VERSION 5.8 ;
BUSBITCHARS "[]" ;
DIVIDERCHAR "/" ;
UNITS
    DATABASE MICRONS 1000 ;
END UNITS

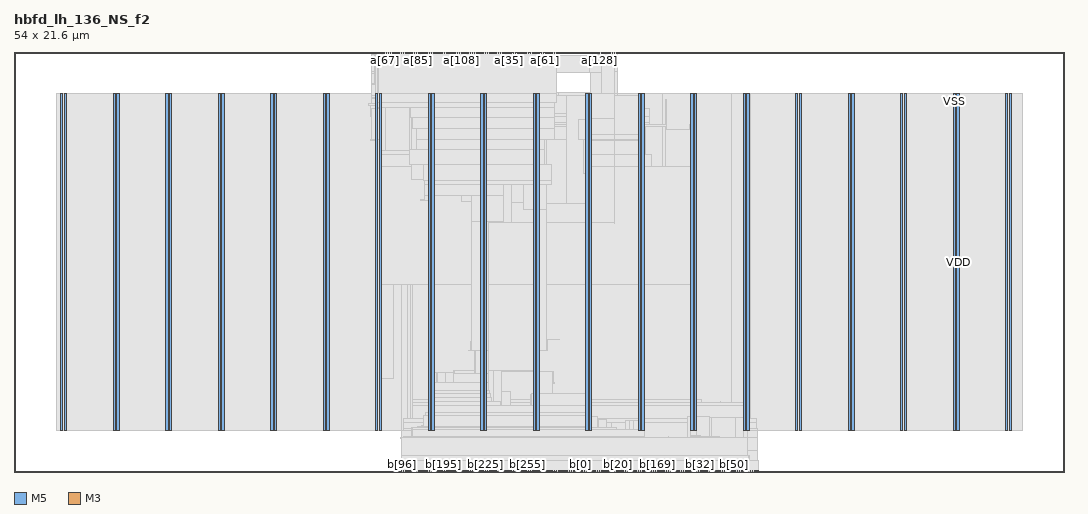
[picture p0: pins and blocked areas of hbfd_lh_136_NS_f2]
MACRO hbfd_lh_136_NS_f2
  FOREIGN hbfd_lh_136_NS_f2 0 0 ;
  CLASS BLOCK ;
  SIZE 54 BY 21.6 ;
  PIN a[0]
    DIRECTION INPUT ;
    USE SIGNAL ;
    PORT
      LAYER M5 ;
        RECT  24.912 21.516 24.936 21.6 ;
    END
  END a[0]
  PIN a[100]
    DIRECTION INPUT ;
    USE SIGNAL ;
    PORT
      LAYER M5 ;
        RECT  22.224 21.516 22.248 21.6 ;
    END
  END a[100]
  PIN a[101]
    DIRECTION INPUT ;
    USE SIGNAL ;
    PORT
      LAYER M5 ;
        RECT  22.32 21.516 22.344 21.6 ;
    END
  END a[101]
  PIN a[102]
    DIRECTION INPUT ;
    USE SIGNAL ;
    PORT
      LAYER M5 ;
        RECT  22.416 21.516 22.44 21.6 ;
    END
  END a[102]
  PIN a[103]
    DIRECTION INPUT ;
    USE SIGNAL ;
    PORT
      LAYER M5 ;
        RECT  22.512 21.516 22.536 21.6 ;
    END
  END a[103]
  PIN a[104]
    DIRECTION INPUT ;
    USE SIGNAL ;
    PORT
      LAYER M5 ;
        RECT  22.608 21.516 22.632 21.6 ;
    END
  END a[104]
  PIN a[105]
    DIRECTION INPUT ;
    USE SIGNAL ;
    PORT
      LAYER M5 ;
        RECT  22.704 21.516 22.728 21.6 ;
    END
  END a[105]
  PIN a[106]
    DIRECTION INPUT ;
    USE SIGNAL ;
    PORT
      LAYER M5 ;
        RECT  22.8 21.516 22.824 21.6 ;
    END
  END a[106]
  PIN a[107]
    DIRECTION INPUT ;
    USE SIGNAL ;
    PORT
      LAYER M5 ;
        RECT  22.896 21.516 22.92 21.6 ;
    END
  END a[107]
  PIN a[108]
    DIRECTION INPUT ;
    USE SIGNAL ;
    PORT
      LAYER M5 ;
        RECT  22.992 21.516 23.016 21.6 ;
    END
  END a[108]
  PIN a[109]
    DIRECTION INPUT ;
    USE SIGNAL ;
    PORT
      LAYER M5 ;
        RECT  23.088 21.516 23.112 21.6 ;
    END
  END a[109]
  PIN a[10]
    DIRECTION INPUT ;
    USE SIGNAL ;
    PORT
      LAYER M5 ;
        RECT  25.872 21.516 25.896 21.6 ;
    END
  END a[10]
  PIN a[110]
    DIRECTION INPUT ;
    USE SIGNAL ;
    PORT
      LAYER M5 ;
        RECT  23.184 21.516 23.208 21.6 ;
    END
  END a[110]
  PIN a[111]
    DIRECTION INPUT ;
    USE SIGNAL ;
    PORT
      LAYER M5 ;
        RECT  23.28 21.516 23.304 21.6 ;
    END
  END a[111]
  PIN a[112]
    DIRECTION INPUT ;
    USE SIGNAL ;
    PORT
      LAYER M5 ;
        RECT  23.376 21.516 23.4 21.6 ;
    END
  END a[112]
  PIN a[113]
    DIRECTION INPUT ;
    USE SIGNAL ;
    PORT
      LAYER M5 ;
        RECT  23.472 21.516 23.496 21.6 ;
    END
  END a[113]
  PIN a[114]
    DIRECTION INPUT ;
    USE SIGNAL ;
    PORT
      LAYER M5 ;
        RECT  23.568 21.516 23.592 21.6 ;
    END
  END a[114]
  PIN a[115]
    DIRECTION INPUT ;
    USE SIGNAL ;
    PORT
      LAYER M5 ;
        RECT  23.664 21.516 23.688 21.6 ;
    END
  END a[115]
  PIN a[116]
    DIRECTION INPUT ;
    USE SIGNAL ;
    PORT
      LAYER M5 ;
        RECT  23.76 21.516 23.784 21.6 ;
    END
  END a[116]
  PIN a[117]
    DIRECTION INPUT ;
    USE SIGNAL ;
    PORT
      LAYER M5 ;
        RECT  23.856 21.516 23.88 21.6 ;
    END
  END a[117]
  PIN a[118]
    DIRECTION INPUT ;
    USE SIGNAL ;
    PORT
      LAYER M5 ;
        RECT  23.952 21.516 23.976 21.6 ;
    END
  END a[118]
  PIN a[119]
    DIRECTION INPUT ;
    USE SIGNAL ;
    PORT
      LAYER M5 ;
        RECT  24.048 21.516 24.072 21.6 ;
    END
  END a[119]
  PIN a[11]
    DIRECTION INPUT ;
    USE SIGNAL ;
    PORT
      LAYER M5 ;
        RECT  25.968 21.516 25.992 21.6 ;
    END
  END a[11]
  PIN a[120]
    DIRECTION INPUT ;
    USE SIGNAL ;
    PORT
      LAYER M5 ;
        RECT  24.144 21.516 24.168 21.6 ;
    END
  END a[120]
  PIN a[121]
    DIRECTION INPUT ;
    USE SIGNAL ;
    PORT
      LAYER M5 ;
        RECT  24.24 21.516 24.264 21.6 ;
    END
  END a[121]
  PIN a[122]
    DIRECTION INPUT ;
    USE SIGNAL ;
    PORT
      LAYER M5 ;
        RECT  24.336 21.516 24.36 21.6 ;
    END
  END a[122]
  PIN a[123]
    DIRECTION INPUT ;
    USE SIGNAL ;
    PORT
      LAYER M5 ;
        RECT  24.432 21.516 24.456 21.6 ;
    END
  END a[123]
  PIN a[124]
    DIRECTION INPUT ;
    USE SIGNAL ;
    PORT
      LAYER M5 ;
        RECT  24.528 21.516 24.552 21.6 ;
    END
  END a[124]
  PIN a[125]
    DIRECTION INPUT ;
    USE SIGNAL ;
    PORT
      LAYER M5 ;
        RECT  24.624 21.516 24.648 21.6 ;
    END
  END a[125]
  PIN a[126]
    DIRECTION INPUT ;
    USE SIGNAL ;
    PORT
      LAYER M5 ;
        RECT  24.72 21.516 24.744 21.6 ;
    END
  END a[126]
  PIN a[127]
    DIRECTION INPUT ;
    USE SIGNAL ;
    PORT
      LAYER M5 ;
        RECT  24.816 21.516 24.84 21.6 ;
    END
  END a[127]
  PIN a[128]
    DIRECTION INPUT ;
    USE SIGNAL ;
    PORT
      LAYER M5 ;
        RECT  30.096 21.516 30.12 21.6 ;
    END
  END a[128]
  PIN a[129]
    DIRECTION INPUT ;
    USE SIGNAL ;
    PORT
      LAYER M5 ;
        RECT  30.192 21.516 30.216 21.6 ;
    END
  END a[129]
  PIN a[12]
    DIRECTION INPUT ;
    USE SIGNAL ;
    PORT
      LAYER M5 ;
        RECT  26.064 21.516 26.088 21.6 ;
    END
  END a[12]
  PIN a[130]
    DIRECTION INPUT ;
    USE SIGNAL ;
    PORT
      LAYER M5 ;
        RECT  30.288 21.516 30.312 21.6 ;
    END
  END a[130]
  PIN a[131]
    DIRECTION INPUT ;
    USE SIGNAL ;
    PORT
      LAYER M5 ;
        RECT  30.384 21.516 30.408 21.6 ;
    END
  END a[131]
  PIN a[132]
    DIRECTION INPUT ;
    USE SIGNAL ;
    PORT
      LAYER M5 ;
        RECT  30.48 21.516 30.504 21.6 ;
    END
  END a[132]
  PIN a[133]
    DIRECTION INPUT ;
    USE SIGNAL ;
    PORT
      LAYER M5 ;
        RECT  30.576 21.516 30.6 21.6 ;
    END
  END a[133]
  PIN a[134]
    DIRECTION INPUT ;
    USE SIGNAL ;
    PORT
      LAYER M5 ;
        RECT  30.672 21.516 30.696 21.6 ;
    END
  END a[134]
  PIN a[135]
    DIRECTION INPUT ;
    USE SIGNAL ;
    PORT
      LAYER M5 ;
        RECT  30.768 21.516 30.792 21.6 ;
    END
  END a[135]
  PIN a[13]
    DIRECTION INPUT ;
    USE SIGNAL ;
    PORT
      LAYER M5 ;
        RECT  26.16 21.516 26.184 21.6 ;
    END
  END a[13]
  PIN a[14]
    DIRECTION INPUT ;
    USE SIGNAL ;
    PORT
      LAYER M5 ;
        RECT  26.256 21.516 26.28 21.6 ;
    END
  END a[14]
  PIN a[15]
    DIRECTION INPUT ;
    USE SIGNAL ;
    PORT
      LAYER M5 ;
        RECT  26.352 21.516 26.376 21.6 ;
    END
  END a[15]
  PIN a[16]
    DIRECTION INPUT ;
    USE SIGNAL ;
    PORT
      LAYER M5 ;
        RECT  26.448 21.516 26.472 21.6 ;
    END
  END a[16]
  PIN a[17]
    DIRECTION INPUT ;
    USE SIGNAL ;
    PORT
      LAYER M5 ;
        RECT  26.544 21.516 26.568 21.6 ;
    END
  END a[17]
  PIN a[18]
    DIRECTION INPUT ;
    USE SIGNAL ;
    PORT
      LAYER M5 ;
        RECT  26.64 21.516 26.664 21.6 ;
    END
  END a[18]
  PIN a[19]
    DIRECTION INPUT ;
    USE SIGNAL ;
    PORT
      LAYER M5 ;
        RECT  26.736 21.516 26.76 21.6 ;
    END
  END a[19]
  PIN a[1]
    DIRECTION INPUT ;
    USE SIGNAL ;
    PORT
      LAYER M5 ;
        RECT  25.008 21.516 25.032 21.6 ;
    END
  END a[1]
  PIN a[20]
    DIRECTION INPUT ;
    USE SIGNAL ;
    PORT
      LAYER M5 ;
        RECT  26.832 21.516 26.856 21.6 ;
    END
  END a[20]
  PIN a[21]
    DIRECTION INPUT ;
    USE SIGNAL ;
    PORT
      LAYER M5 ;
        RECT  26.928 21.516 26.952 21.6 ;
    END
  END a[21]
  PIN a[22]
    DIRECTION INPUT ;
    USE SIGNAL ;
    PORT
      LAYER M5 ;
        RECT  27.024 21.516 27.048 21.6 ;
    END
  END a[22]
  PIN a[23]
    DIRECTION INPUT ;
    USE SIGNAL ;
    PORT
      LAYER M5 ;
        RECT  27.12 21.516 27.144 21.6 ;
    END
  END a[23]
  PIN a[24]
    DIRECTION INPUT ;
    USE SIGNAL ;
    PORT
      LAYER M5 ;
        RECT  27.216 21.516 27.24 21.6 ;
    END
  END a[24]
  PIN a[25]
    DIRECTION INPUT ;
    USE SIGNAL ;
    PORT
      LAYER M5 ;
        RECT  27.312 21.516 27.336 21.6 ;
    END
  END a[25]
  PIN a[26]
    DIRECTION INPUT ;
    USE SIGNAL ;
    PORT
      LAYER M5 ;
        RECT  27.408 21.516 27.432 21.6 ;
    END
  END a[26]
  PIN a[27]
    DIRECTION INPUT ;
    USE SIGNAL ;
    PORT
      LAYER M5 ;
        RECT  27.504 21.516 27.528 21.6 ;
    END
  END a[27]
  PIN a[28]
    DIRECTION INPUT ;
    USE SIGNAL ;
    PORT
      LAYER M5 ;
        RECT  27.6 21.516 27.624 21.6 ;
    END
  END a[28]
  PIN a[29]
    DIRECTION INPUT ;
    USE SIGNAL ;
    PORT
      LAYER M5 ;
        RECT  27.696 21.516 27.72 21.6 ;
    END
  END a[29]
  PIN a[2]
    DIRECTION INPUT ;
    USE SIGNAL ;
    PORT
      LAYER M5 ;
        RECT  25.104 21.516 25.128 21.6 ;
    END
  END a[2]
  PIN a[30]
    DIRECTION INPUT ;
    USE SIGNAL ;
    PORT
      LAYER M5 ;
        RECT  27.792 21.516 27.816 21.6 ;
    END
  END a[30]
  PIN a[31]
    DIRECTION INPUT ;
    USE SIGNAL ;
    PORT
      LAYER M5 ;
        RECT  27.888 21.516 27.912 21.6 ;
    END
  END a[31]
  PIN a[32]
    DIRECTION INPUT ;
    USE SIGNAL ;
    PORT
      LAYER M3 ;
        RECT  25.236 21.563 25.254 21.6 ;
    END
  END a[32]
  PIN a[33]
    DIRECTION INPUT ;
    USE SIGNAL ;
    PORT
      LAYER M3 ;
        RECT  25.308 21.563 25.326 21.6 ;
    END
  END a[33]
  PIN a[34]
    DIRECTION INPUT ;
    USE SIGNAL ;
    PORT
      LAYER M3 ;
        RECT  25.38 21.563 25.398 21.6 ;
    END
  END a[34]
  PIN a[35]
    DIRECTION INPUT ;
    USE SIGNAL ;
    PORT
      LAYER M3 ;
        RECT  25.452 21.563 25.47 21.6 ;
    END
  END a[35]
  PIN a[36]
    DIRECTION INPUT ;
    USE SIGNAL ;
    PORT
      LAYER M3 ;
        RECT  25.524 21.563 25.542 21.6 ;
    END
  END a[36]
  PIN a[37]
    DIRECTION INPUT ;
    USE SIGNAL ;
    PORT
      LAYER M3 ;
        RECT  25.596 21.563 25.614 21.6 ;
    END
  END a[37]
  PIN a[38]
    DIRECTION INPUT ;
    USE SIGNAL ;
    PORT
      LAYER M3 ;
        RECT  25.668 21.563 25.686 21.6 ;
    END
  END a[38]
  PIN a[39]
    DIRECTION INPUT ;
    USE SIGNAL ;
    PORT
      LAYER M3 ;
        RECT  25.74 21.563 25.758 21.6 ;
    END
  END a[39]
  PIN a[3]
    DIRECTION INPUT ;
    USE SIGNAL ;
    PORT
      LAYER M5 ;
        RECT  25.2 21.516 25.224 21.6 ;
    END
  END a[3]
  PIN a[40]
    DIRECTION INPUT ;
    USE SIGNAL ;
    PORT
      LAYER M3 ;
        RECT  25.812 21.563 25.83 21.6 ;
    END
  END a[40]
  PIN a[41]
    DIRECTION INPUT ;
    USE SIGNAL ;
    PORT
      LAYER M3 ;
        RECT  25.884 21.563 25.902 21.6 ;
    END
  END a[41]
  PIN a[42]
    DIRECTION INPUT ;
    USE SIGNAL ;
    PORT
      LAYER M3 ;
        RECT  25.956 21.563 25.974 21.6 ;
    END
  END a[42]
  PIN a[43]
    DIRECTION INPUT ;
    USE SIGNAL ;
    PORT
      LAYER M3 ;
        RECT  26.028 21.563 26.046 21.6 ;
    END
  END a[43]
  PIN a[44]
    DIRECTION INPUT ;
    USE SIGNAL ;
    PORT
      LAYER M3 ;
        RECT  26.1 21.563 26.118 21.6 ;
    END
  END a[44]
  PIN a[45]
    DIRECTION INPUT ;
    USE SIGNAL ;
    PORT
      LAYER M3 ;
        RECT  26.172 21.563 26.19 21.6 ;
    END
  END a[45]
  PIN a[46]
    DIRECTION INPUT ;
    USE SIGNAL ;
    PORT
      LAYER M3 ;
        RECT  26.244 21.563 26.262 21.6 ;
    END
  END a[46]
  PIN a[47]
    DIRECTION INPUT ;
    USE SIGNAL ;
    PORT
      LAYER M3 ;
        RECT  26.316 21.563 26.334 21.6 ;
    END
  END a[47]
  PIN a[48]
    DIRECTION INPUT ;
    USE SIGNAL ;
    PORT
      LAYER M3 ;
        RECT  26.388 21.563 26.406 21.6 ;
    END
  END a[48]
  PIN a[49]
    DIRECTION INPUT ;
    USE SIGNAL ;
    PORT
      LAYER M3 ;
        RECT  26.46 21.563 26.478 21.6 ;
    END
  END a[49]
  PIN a[4]
    DIRECTION INPUT ;
    USE SIGNAL ;
    PORT
      LAYER M5 ;
        RECT  25.296 21.516 25.32 21.6 ;
    END
  END a[4]
  PIN a[50]
    DIRECTION INPUT ;
    USE SIGNAL ;
    PORT
      LAYER M3 ;
        RECT  26.532 21.563 26.55 21.6 ;
    END
  END a[50]
  PIN a[51]
    DIRECTION INPUT ;
    USE SIGNAL ;
    PORT
      LAYER M3 ;
        RECT  26.604 21.563 26.622 21.6 ;
    END
  END a[51]
  PIN a[52]
    DIRECTION INPUT ;
    USE SIGNAL ;
    PORT
      LAYER M3 ;
        RECT  26.676 21.563 26.694 21.6 ;
    END
  END a[52]
  PIN a[53]
    DIRECTION INPUT ;
    USE SIGNAL ;
    PORT
      LAYER M3 ;
        RECT  26.748 21.563 26.766 21.6 ;
    END
  END a[53]
  PIN a[54]
    DIRECTION INPUT ;
    USE SIGNAL ;
    PORT
      LAYER M3 ;
        RECT  26.82 21.563 26.838 21.6 ;
    END
  END a[54]
  PIN a[55]
    DIRECTION INPUT ;
    USE SIGNAL ;
    PORT
      LAYER M3 ;
        RECT  26.892 21.563 26.91 21.6 ;
    END
  END a[55]
  PIN a[56]
    DIRECTION INPUT ;
    USE SIGNAL ;
    PORT
      LAYER M3 ;
        RECT  26.964 21.563 26.982 21.6 ;
    END
  END a[56]
  PIN a[57]
    DIRECTION INPUT ;
    USE SIGNAL ;
    PORT
      LAYER M3 ;
        RECT  27.036 21.563 27.054 21.6 ;
    END
  END a[57]
  PIN a[58]
    DIRECTION INPUT ;
    USE SIGNAL ;
    PORT
      LAYER M3 ;
        RECT  27.108 21.563 27.126 21.6 ;
    END
  END a[58]
  PIN a[59]
    DIRECTION INPUT ;
    USE SIGNAL ;
    PORT
      LAYER M3 ;
        RECT  27.18 21.563 27.198 21.6 ;
    END
  END a[59]
  PIN a[5]
    DIRECTION INPUT ;
    USE SIGNAL ;
    PORT
      LAYER M5 ;
        RECT  25.392 21.516 25.416 21.6 ;
    END
  END a[5]
  PIN a[60]
    DIRECTION INPUT ;
    USE SIGNAL ;
    PORT
      LAYER M3 ;
        RECT  27.252 21.563 27.27 21.6 ;
    END
  END a[60]
  PIN a[61]
    DIRECTION INPUT ;
    USE SIGNAL ;
    PORT
      LAYER M3 ;
        RECT  27.324 21.563 27.342 21.6 ;
    END
  END a[61]
  PIN a[62]
    DIRECTION INPUT ;
    USE SIGNAL ;
    PORT
      LAYER M3 ;
        RECT  27.396 21.563 27.414 21.6 ;
    END
  END a[62]
  PIN a[63]
    DIRECTION INPUT ;
    USE SIGNAL ;
    PORT
      LAYER M3 ;
        RECT  27.468 21.563 27.486 21.6 ;
    END
  END a[63]
  PIN a[64]
    DIRECTION INPUT ;
    USE SIGNAL ;
    PORT
      LAYER M5 ;
        RECT  18.768 21.516 18.792 21.6 ;
    END
  END a[64]
  PIN a[65]
    DIRECTION INPUT ;
    USE SIGNAL ;
    PORT
      LAYER M5 ;
        RECT  18.864 21.516 18.888 21.6 ;
    END
  END a[65]
  PIN a[66]
    DIRECTION INPUT ;
    USE SIGNAL ;
    PORT
      LAYER M5 ;
        RECT  18.96 21.516 18.984 21.6 ;
    END
  END a[66]
  PIN a[67]
    DIRECTION INPUT ;
    USE SIGNAL ;
    PORT
      LAYER M5 ;
        RECT  19.056 21.516 19.08 21.6 ;
    END
  END a[67]
  PIN a[68]
    DIRECTION INPUT ;
    USE SIGNAL ;
    PORT
      LAYER M5 ;
        RECT  19.152 21.516 19.176 21.6 ;
    END
  END a[68]
  PIN a[69]
    DIRECTION INPUT ;
    USE SIGNAL ;
    PORT
      LAYER M5 ;
        RECT  19.248 21.516 19.272 21.6 ;
    END
  END a[69]
  PIN a[6]
    DIRECTION INPUT ;
    USE SIGNAL ;
    PORT
      LAYER M5 ;
        RECT  25.488 21.516 25.512 21.6 ;
    END
  END a[6]
  PIN a[70]
    DIRECTION INPUT ;
    USE SIGNAL ;
    PORT
      LAYER M5 ;
        RECT  19.344 21.516 19.368 21.6 ;
    END
  END a[70]
  PIN a[71]
    DIRECTION INPUT ;
    USE SIGNAL ;
    PORT
      LAYER M5 ;
        RECT  19.44 21.516 19.464 21.6 ;
    END
  END a[71]
  PIN a[72]
    DIRECTION INPUT ;
    USE SIGNAL ;
    PORT
      LAYER M5 ;
        RECT  19.536 21.516 19.56 21.6 ;
    END
  END a[72]
  PIN a[73]
    DIRECTION INPUT ;
    USE SIGNAL ;
    PORT
      LAYER M5 ;
        RECT  19.632 21.516 19.656 21.6 ;
    END
  END a[73]
  PIN a[74]
    DIRECTION INPUT ;
    USE SIGNAL ;
    PORT
      LAYER M5 ;
        RECT  19.728 21.516 19.752 21.6 ;
    END
  END a[74]
  PIN a[75]
    DIRECTION INPUT ;
    USE SIGNAL ;
    PORT
      LAYER M5 ;
        RECT  19.824 21.516 19.848 21.6 ;
    END
  END a[75]
  PIN a[76]
    DIRECTION INPUT ;
    USE SIGNAL ;
    PORT
      LAYER M5 ;
        RECT  19.92 21.516 19.944 21.6 ;
    END
  END a[76]
  PIN a[77]
    DIRECTION INPUT ;
    USE SIGNAL ;
    PORT
      LAYER M5 ;
        RECT  20.016 21.516 20.04 21.6 ;
    END
  END a[77]
  PIN a[78]
    DIRECTION INPUT ;
    USE SIGNAL ;
    PORT
      LAYER M5 ;
        RECT  20.112 21.516 20.136 21.6 ;
    END
  END a[78]
  PIN a[79]
    DIRECTION INPUT ;
    USE SIGNAL ;
    PORT
      LAYER M5 ;
        RECT  20.208 21.516 20.232 21.6 ;
    END
  END a[79]
  PIN a[7]
    DIRECTION INPUT ;
    USE SIGNAL ;
    PORT
      LAYER M5 ;
        RECT  25.584 21.516 25.608 21.6 ;
    END
  END a[7]
  PIN a[80]
    DIRECTION INPUT ;
    USE SIGNAL ;
    PORT
      LAYER M5 ;
        RECT  20.304 21.516 20.328 21.6 ;
    END
  END a[80]
  PIN a[81]
    DIRECTION INPUT ;
    USE SIGNAL ;
    PORT
      LAYER M5 ;
        RECT  20.4 21.516 20.424 21.6 ;
    END
  END a[81]
  PIN a[82]
    DIRECTION INPUT ;
    USE SIGNAL ;
    PORT
      LAYER M5 ;
        RECT  20.496 21.516 20.52 21.6 ;
    END
  END a[82]
  PIN a[83]
    DIRECTION INPUT ;
    USE SIGNAL ;
    PORT
      LAYER M5 ;
        RECT  20.592 21.516 20.616 21.6 ;
    END
  END a[83]
  PIN a[84]
    DIRECTION INPUT ;
    USE SIGNAL ;
    PORT
      LAYER M5 ;
        RECT  20.688 21.516 20.712 21.6 ;
    END
  END a[84]
  PIN a[85]
    DIRECTION INPUT ;
    USE SIGNAL ;
    PORT
      LAYER M5 ;
        RECT  20.784 21.516 20.808 21.6 ;
    END
  END a[85]
  PIN a[86]
    DIRECTION INPUT ;
    USE SIGNAL ;
    PORT
      LAYER M5 ;
        RECT  20.88 21.516 20.904 21.6 ;
    END
  END a[86]
  PIN a[87]
    DIRECTION INPUT ;
    USE SIGNAL ;
    PORT
      LAYER M5 ;
        RECT  20.976 21.516 21 21.6 ;
    END
  END a[87]
  PIN a[88]
    DIRECTION INPUT ;
    USE SIGNAL ;
    PORT
      LAYER M5 ;
        RECT  21.072 21.516 21.096 21.6 ;
    END
  END a[88]
  PIN a[89]
    DIRECTION INPUT ;
    USE SIGNAL ;
    PORT
      LAYER M5 ;
        RECT  21.168 21.516 21.192 21.6 ;
    END
  END a[89]
  PIN a[8]
    DIRECTION INPUT ;
    USE SIGNAL ;
    PORT
      LAYER M5 ;
        RECT  25.68 21.516 25.704 21.6 ;
    END
  END a[8]
  PIN a[90]
    DIRECTION INPUT ;
    USE SIGNAL ;
    PORT
      LAYER M5 ;
        RECT  21.264 21.516 21.288 21.6 ;
    END
  END a[90]
  PIN a[91]
    DIRECTION INPUT ;
    USE SIGNAL ;
    PORT
      LAYER M5 ;
        RECT  21.36 21.516 21.384 21.6 ;
    END
  END a[91]
  PIN a[92]
    DIRECTION INPUT ;
    USE SIGNAL ;
    PORT
      LAYER M5 ;
        RECT  21.456 21.516 21.48 21.6 ;
    END
  END a[92]
  PIN a[93]
    DIRECTION INPUT ;
    USE SIGNAL ;
    PORT
      LAYER M5 ;
        RECT  21.552 21.516 21.576 21.6 ;
    END
  END a[93]
  PIN a[94]
    DIRECTION INPUT ;
    USE SIGNAL ;
    PORT
      LAYER M5 ;
        RECT  21.648 21.516 21.672 21.6 ;
    END
  END a[94]
  PIN a[95]
    DIRECTION INPUT ;
    USE SIGNAL ;
    PORT
      LAYER M5 ;
        RECT  21.744 21.516 21.768 21.6 ;
    END
  END a[95]
  PIN a[96]
    DIRECTION INPUT ;
    USE SIGNAL ;
    PORT
      LAYER M5 ;
        RECT  21.84 21.516 21.864 21.6 ;
    END
  END a[96]
  PIN a[97]
    DIRECTION INPUT ;
    USE SIGNAL ;
    PORT
      LAYER M5 ;
        RECT  21.936 21.516 21.96 21.6 ;
    END
  END a[97]
  PIN a[98]
    DIRECTION INPUT ;
    USE SIGNAL ;
    PORT
      LAYER M5 ;
        RECT  22.032 21.516 22.056 21.6 ;
    END
  END a[98]
  PIN a[99]
    DIRECTION INPUT ;
    USE SIGNAL ;
    PORT
      LAYER M5 ;
        RECT  22.128 21.516 22.152 21.6 ;
    END
  END a[99]
  PIN a[9]
    DIRECTION INPUT ;
    USE SIGNAL ;
    PORT
      LAYER M5 ;
        RECT  25.776 21.516 25.8 21.6 ;
    END
  END a[9]
  PIN b[0]
    DIRECTION OUTPUT ;
    USE SIGNAL ;
    PORT
      LAYER M5 ;
        RECT  29.136 0 29.16 0.084 ;
    END
  END b[0]
  PIN b[100]
    DIRECTION OUTPUT ;
    USE SIGNAL ;
    PORT
      LAYER M5 ;
        RECT  20.304 0 20.328 0.084 ;
    END
  END b[100]
  PIN b[101]
    DIRECTION OUTPUT ;
    USE SIGNAL ;
    PORT
      LAYER M5 ;
        RECT  20.4 0 20.424 0.084 ;
    END
  END b[101]
  PIN b[102]
    DIRECTION OUTPUT ;
    USE SIGNAL ;
    PORT
      LAYER M5 ;
        RECT  20.496 0 20.52 0.084 ;
    END
  END b[102]
  PIN b[103]
    DIRECTION OUTPUT ;
    USE SIGNAL ;
    PORT
      LAYER M5 ;
        RECT  20.592 0 20.616 0.084 ;
    END
  END b[103]
  PIN b[104]
    DIRECTION OUTPUT ;
    USE SIGNAL ;
    PORT
      LAYER M5 ;
        RECT  20.688 0 20.712 0.084 ;
    END
  END b[104]
  PIN b[105]
    DIRECTION OUTPUT ;
    USE SIGNAL ;
    PORT
      LAYER M5 ;
        RECT  20.784 0 20.808 0.084 ;
    END
  END b[105]
  PIN b[106]
    DIRECTION OUTPUT ;
    USE SIGNAL ;
    PORT
      LAYER M5 ;
        RECT  20.88 0 20.904 0.084 ;
    END
  END b[106]
  PIN b[107]
    DIRECTION OUTPUT ;
    USE SIGNAL ;
    PORT
      LAYER M5 ;
        RECT  20.976 0 21 0.084 ;
    END
  END b[107]
  PIN b[108]
    DIRECTION OUTPUT ;
    USE SIGNAL ;
    PORT
      LAYER M5 ;
        RECT  21.072 0 21.096 0.084 ;
    END
  END b[108]
  PIN b[109]
    DIRECTION OUTPUT ;
    USE SIGNAL ;
    PORT
      LAYER M5 ;
        RECT  21.168 0 21.192 0.084 ;
    END
  END b[109]
  PIN b[10]
    DIRECTION OUTPUT ;
    USE SIGNAL ;
    PORT
      LAYER M5 ;
        RECT  30.096 0 30.12 0.084 ;
    END
  END b[10]
  PIN b[110]
    DIRECTION OUTPUT ;
    USE SIGNAL ;
    PORT
      LAYER M5 ;
        RECT  21.264 0 21.288 0.084 ;
    END
  END b[110]
  PIN b[111]
    DIRECTION OUTPUT ;
    USE SIGNAL ;
    PORT
      LAYER M5 ;
        RECT  21.36 0 21.384 0.084 ;
    END
  END b[111]
  PIN b[112]
    DIRECTION OUTPUT ;
    USE SIGNAL ;
    PORT
      LAYER M5 ;
        RECT  21.456 0 21.48 0.084 ;
    END
  END b[112]
  PIN b[113]
    DIRECTION OUTPUT ;
    USE SIGNAL ;
    PORT
      LAYER M5 ;
        RECT  21.552 0 21.576 0.084 ;
    END
  END b[113]
  PIN b[114]
    DIRECTION OUTPUT ;
    USE SIGNAL ;
    PORT
      LAYER M5 ;
        RECT  21.648 0 21.672 0.084 ;
    END
  END b[114]
  PIN b[115]
    DIRECTION OUTPUT ;
    USE SIGNAL ;
    PORT
      LAYER M5 ;
        RECT  21.744 0 21.768 0.084 ;
    END
  END b[115]
  PIN b[116]
    DIRECTION OUTPUT ;
    USE SIGNAL ;
    PORT
      LAYER M5 ;
        RECT  21.84 0 21.864 0.084 ;
    END
  END b[116]
  PIN b[117]
    DIRECTION OUTPUT ;
    USE SIGNAL ;
    PORT
      LAYER M5 ;
        RECT  21.936 0 21.96 0.084 ;
    END
  END b[117]
  PIN b[118]
    DIRECTION OUTPUT ;
    USE SIGNAL ;
    PORT
      LAYER M5 ;
        RECT  22.032 0 22.056 0.084 ;
    END
  END b[118]
  PIN b[119]
    DIRECTION OUTPUT ;
    USE SIGNAL ;
    PORT
      LAYER M5 ;
        RECT  22.128 0 22.152 0.084 ;
    END
  END b[119]
  PIN b[11]
    DIRECTION OUTPUT ;
    USE SIGNAL ;
    PORT
      LAYER M5 ;
        RECT  30.192 0 30.216 0.084 ;
    END
  END b[11]
  PIN b[120]
    DIRECTION OUTPUT ;
    USE SIGNAL ;
    PORT
      LAYER M5 ;
        RECT  22.224 0 22.248 0.084 ;
    END
  END b[120]
  PIN b[121]
    DIRECTION OUTPUT ;
    USE SIGNAL ;
    PORT
      LAYER M5 ;
        RECT  22.32 0 22.344 0.084 ;
    END
  END b[121]
  PIN b[122]
    DIRECTION OUTPUT ;
    USE SIGNAL ;
    PORT
      LAYER M5 ;
        RECT  22.416 0 22.44 0.084 ;
    END
  END b[122]
  PIN b[123]
    DIRECTION OUTPUT ;
    USE SIGNAL ;
    PORT
      LAYER M5 ;
        RECT  22.512 0 22.536 0.084 ;
    END
  END b[123]
  PIN b[124]
    DIRECTION OUTPUT ;
    USE SIGNAL ;
    PORT
      LAYER M5 ;
        RECT  22.608 0 22.632 0.084 ;
    END
  END b[124]
  PIN b[125]
    DIRECTION OUTPUT ;
    USE SIGNAL ;
    PORT
      LAYER M5 ;
        RECT  22.704 0 22.728 0.084 ;
    END
  END b[125]
  PIN b[126]
    DIRECTION OUTPUT ;
    USE SIGNAL ;
    PORT
      LAYER M5 ;
        RECT  22.8 0 22.824 0.084 ;
    END
  END b[126]
  PIN b[127]
    DIRECTION OUTPUT ;
    USE SIGNAL ;
    PORT
      LAYER M5 ;
        RECT  22.896 0 22.92 0.084 ;
    END
  END b[127]
  PIN b[128]
    DIRECTION OUTPUT ;
    USE SIGNAL ;
    PORT
      LAYER M5 ;
        RECT  26.064 0 26.088 0.084 ;
    END
  END b[128]
  PIN b[129]
    DIRECTION OUTPUT ;
    USE SIGNAL ;
    PORT
      LAYER M5 ;
        RECT  26.16 0 26.184 0.084 ;
    END
  END b[129]
  PIN b[12]
    DIRECTION OUTPUT ;
    USE SIGNAL ;
    PORT
      LAYER M5 ;
        RECT  30.288 0 30.312 0.084 ;
    END
  END b[12]
  PIN b[130]
    DIRECTION OUTPUT ;
    USE SIGNAL ;
    PORT
      LAYER M5 ;
        RECT  26.256 0 26.28 0.084 ;
    END
  END b[130]
  PIN b[131]
    DIRECTION OUTPUT ;
    USE SIGNAL ;
    PORT
      LAYER M5 ;
        RECT  26.352 0 26.376 0.084 ;
    END
  END b[131]
  PIN b[132]
    DIRECTION OUTPUT ;
    USE SIGNAL ;
    PORT
      LAYER M5 ;
        RECT  26.448 0 26.472 0.084 ;
    END
  END b[132]
  PIN b[133]
    DIRECTION OUTPUT ;
    USE SIGNAL ;
    PORT
      LAYER M5 ;
        RECT  26.544 0 26.568 0.084 ;
    END
  END b[133]
  PIN b[134]
    DIRECTION OUTPUT ;
    USE SIGNAL ;
    PORT
      LAYER M5 ;
        RECT  26.64 0 26.664 0.084 ;
    END
  END b[134]
  PIN b[135]
    DIRECTION OUTPUT ;
    USE SIGNAL ;
    PORT
      LAYER M5 ;
        RECT  26.736 0 26.76 0.084 ;
    END
  END b[135]
  PIN b[136]
    DIRECTION OUTPUT ;
    USE SIGNAL ;
    PORT
      LAYER M5 ;
        RECT  26.832 0 26.856 0.084 ;
    END
  END b[136]
  PIN b[137]
    DIRECTION OUTPUT ;
    USE SIGNAL ;
    PORT
      LAYER M5 ;
        RECT  26.928 0 26.952 0.084 ;
    END
  END b[137]
  PIN b[138]
    DIRECTION OUTPUT ;
    USE SIGNAL ;
    PORT
      LAYER M5 ;
        RECT  27.024 0 27.048 0.084 ;
    END
  END b[138]
  PIN b[139]
    DIRECTION OUTPUT ;
    USE SIGNAL ;
    PORT
      LAYER M5 ;
        RECT  27.12 0 27.144 0.084 ;
    END
  END b[139]
  PIN b[13]
    DIRECTION OUTPUT ;
    USE SIGNAL ;
    PORT
      LAYER M5 ;
        RECT  30.384 0 30.408 0.084 ;
    END
  END b[13]
  PIN b[140]
    DIRECTION OUTPUT ;
    USE SIGNAL ;
    PORT
      LAYER M5 ;
        RECT  27.216 0 27.24 0.084 ;
    END
  END b[140]
  PIN b[141]
    DIRECTION OUTPUT ;
    USE SIGNAL ;
    PORT
      LAYER M5 ;
        RECT  27.312 0 27.336 0.084 ;
    END
  END b[141]
  PIN b[142]
    DIRECTION OUTPUT ;
    USE SIGNAL ;
    PORT
      LAYER M5 ;
        RECT  27.408 0 27.432 0.084 ;
    END
  END b[142]
  PIN b[143]
    DIRECTION OUTPUT ;
    USE SIGNAL ;
    PORT
      LAYER M5 ;
        RECT  27.504 0 27.528 0.084 ;
    END
  END b[143]
  PIN b[144]
    DIRECTION OUTPUT ;
    USE SIGNAL ;
    PORT
      LAYER M5 ;
        RECT  27.6 0 27.624 0.084 ;
    END
  END b[144]
  PIN b[145]
    DIRECTION OUTPUT ;
    USE SIGNAL ;
    PORT
      LAYER M5 ;
        RECT  27.696 0 27.72 0.084 ;
    END
  END b[145]
  PIN b[146]
    DIRECTION OUTPUT ;
    USE SIGNAL ;
    PORT
      LAYER M5 ;
        RECT  27.792 0 27.816 0.084 ;
    END
  END b[146]
  PIN b[147]
    DIRECTION OUTPUT ;
    USE SIGNAL ;
    PORT
      LAYER M5 ;
        RECT  27.888 0 27.912 0.084 ;
    END
  END b[147]
  PIN b[148]
    DIRECTION OUTPUT ;
    USE SIGNAL ;
    PORT
      LAYER M5 ;
        RECT  27.984 0 28.008 0.084 ;
    END
  END b[148]
  PIN b[149]
    DIRECTION OUTPUT ;
    USE SIGNAL ;
    PORT
      LAYER M5 ;
        RECT  28.08 0 28.104 0.084 ;
    END
  END b[149]
  PIN b[14]
    DIRECTION OUTPUT ;
    USE SIGNAL ;
    PORT
      LAYER M5 ;
        RECT  30.48 0 30.504 0.084 ;
    END
  END b[14]
  PIN b[150]
    DIRECTION OUTPUT ;
    USE SIGNAL ;
    PORT
      LAYER M5 ;
        RECT  28.176 0 28.2 0.084 ;
    END
  END b[150]
  PIN b[151]
    DIRECTION OUTPUT ;
    USE SIGNAL ;
    PORT
      LAYER M5 ;
        RECT  28.272 0 28.296 0.084 ;
    END
  END b[151]
  PIN b[152]
    DIRECTION OUTPUT ;
    USE SIGNAL ;
    PORT
      LAYER M5 ;
        RECT  28.368 0 28.392 0.084 ;
    END
  END b[152]
  PIN b[153]
    DIRECTION OUTPUT ;
    USE SIGNAL ;
    PORT
      LAYER M5 ;
        RECT  28.464 0 28.488 0.084 ;
    END
  END b[153]
  PIN b[154]
    DIRECTION OUTPUT ;
    USE SIGNAL ;
    PORT
      LAYER M5 ;
        RECT  28.56 0 28.584 0.084 ;
    END
  END b[154]
  PIN b[155]
    DIRECTION OUTPUT ;
    USE SIGNAL ;
    PORT
      LAYER M5 ;
        RECT  28.656 0 28.68 0.084 ;
    END
  END b[155]
  PIN b[156]
    DIRECTION OUTPUT ;
    USE SIGNAL ;
    PORT
      LAYER M5 ;
        RECT  28.752 0 28.776 0.084 ;
    END
  END b[156]
  PIN b[157]
    DIRECTION OUTPUT ;
    USE SIGNAL ;
    PORT
      LAYER M5 ;
        RECT  28.848 0 28.872 0.084 ;
    END
  END b[157]
  PIN b[158]
    DIRECTION OUTPUT ;
    USE SIGNAL ;
    PORT
      LAYER M5 ;
        RECT  28.944 0 28.968 0.084 ;
    END
  END b[158]
  PIN b[159]
    DIRECTION OUTPUT ;
    USE SIGNAL ;
    PORT
      LAYER M5 ;
        RECT  29.04 0 29.064 0.084 ;
    END
  END b[159]
  PIN b[15]
    DIRECTION OUTPUT ;
    USE SIGNAL ;
    PORT
      LAYER M5 ;
        RECT  30.576 0 30.6 0.084 ;
    END
  END b[15]
  PIN b[160]
    DIRECTION OUTPUT ;
    USE SIGNAL ;
    PORT
      LAYER M5 ;
        RECT  32.208 0 32.232 0.084 ;
    END
  END b[160]
  PIN b[161]
    DIRECTION OUTPUT ;
    USE SIGNAL ;
    PORT
      LAYER M5 ;
        RECT  32.304 0 32.328 0.084 ;
    END
  END b[161]
  PIN b[162]
    DIRECTION OUTPUT ;
    USE SIGNAL ;
    PORT
      LAYER M5 ;
        RECT  32.4 0 32.424 0.084 ;
    END
  END b[162]
  PIN b[163]
    DIRECTION OUTPUT ;
    USE SIGNAL ;
    PORT
      LAYER M5 ;
        RECT  32.496 0 32.52 0.084 ;
    END
  END b[163]
  PIN b[164]
    DIRECTION OUTPUT ;
    USE SIGNAL ;
    PORT
      LAYER M5 ;
        RECT  32.592 0 32.616 0.084 ;
    END
  END b[164]
  PIN b[165]
    DIRECTION OUTPUT ;
    USE SIGNAL ;
    PORT
      LAYER M5 ;
        RECT  32.688 0 32.712 0.084 ;
    END
  END b[165]
  PIN b[166]
    DIRECTION OUTPUT ;
    USE SIGNAL ;
    PORT
      LAYER M5 ;
        RECT  32.784 0 32.808 0.084 ;
    END
  END b[166]
  PIN b[167]
    DIRECTION OUTPUT ;
    USE SIGNAL ;
    PORT
      LAYER M5 ;
        RECT  32.88 0 32.904 0.084 ;
    END
  END b[167]
  PIN b[168]
    DIRECTION OUTPUT ;
    USE SIGNAL ;
    PORT
      LAYER M5 ;
        RECT  32.976 0 33 0.084 ;
    END
  END b[168]
  PIN b[169]
    DIRECTION OUTPUT ;
    USE SIGNAL ;
    PORT
      LAYER M5 ;
        RECT  33.072 0 33.096 0.084 ;
    END
  END b[169]
  PIN b[16]
    DIRECTION OUTPUT ;
    USE SIGNAL ;
    PORT
      LAYER M5 ;
        RECT  30.672 0 30.696 0.084 ;
    END
  END b[16]
  PIN b[170]
    DIRECTION OUTPUT ;
    USE SIGNAL ;
    PORT
      LAYER M5 ;
        RECT  33.168 0 33.192 0.084 ;
    END
  END b[170]
  PIN b[171]
    DIRECTION OUTPUT ;
    USE SIGNAL ;
    PORT
      LAYER M5 ;
        RECT  33.264 0 33.288 0.084 ;
    END
  END b[171]
  PIN b[172]
    DIRECTION OUTPUT ;
    USE SIGNAL ;
    PORT
      LAYER M5 ;
        RECT  33.36 0 33.384 0.084 ;
    END
  END b[172]
  PIN b[173]
    DIRECTION OUTPUT ;
    USE SIGNAL ;
    PORT
      LAYER M5 ;
        RECT  33.456 0 33.48 0.084 ;
    END
  END b[173]
  PIN b[174]
    DIRECTION OUTPUT ;
    USE SIGNAL ;
    PORT
      LAYER M5 ;
        RECT  33.552 0 33.576 0.084 ;
    END
  END b[174]
  PIN b[175]
    DIRECTION OUTPUT ;
    USE SIGNAL ;
    PORT
      LAYER M5 ;
        RECT  33.648 0 33.672 0.084 ;
    END
  END b[175]
  PIN b[176]
    DIRECTION OUTPUT ;
    USE SIGNAL ;
    PORT
      LAYER M5 ;
        RECT  33.744 0 33.768 0.084 ;
    END
  END b[176]
  PIN b[177]
    DIRECTION OUTPUT ;
    USE SIGNAL ;
    PORT
      LAYER M5 ;
        RECT  33.84 0 33.864 0.084 ;
    END
  END b[177]
  PIN b[178]
    DIRECTION OUTPUT ;
    USE SIGNAL ;
    PORT
      LAYER M5 ;
        RECT  33.936 0 33.96 0.084 ;
    END
  END b[178]
  PIN b[179]
    DIRECTION OUTPUT ;
    USE SIGNAL ;
    PORT
      LAYER M5 ;
        RECT  34.032 0 34.056 0.084 ;
    END
  END b[179]
  PIN b[17]
    DIRECTION OUTPUT ;
    USE SIGNAL ;
    PORT
      LAYER M5 ;
        RECT  30.768 0 30.792 0.084 ;
    END
  END b[17]
  PIN b[180]
    DIRECTION OUTPUT ;
    USE SIGNAL ;
    PORT
      LAYER M5 ;
        RECT  34.128 0 34.152 0.084 ;
    END
  END b[180]
  PIN b[181]
    DIRECTION OUTPUT ;
    USE SIGNAL ;
    PORT
      LAYER M5 ;
        RECT  34.224 0 34.248 0.084 ;
    END
  END b[181]
  PIN b[182]
    DIRECTION OUTPUT ;
    USE SIGNAL ;
    PORT
      LAYER M5 ;
        RECT  34.32 0 34.344 0.084 ;
    END
  END b[182]
  PIN b[183]
    DIRECTION OUTPUT ;
    USE SIGNAL ;
    PORT
      LAYER M5 ;
        RECT  34.416 0 34.44 0.084 ;
    END
  END b[183]
  PIN b[184]
    DIRECTION OUTPUT ;
    USE SIGNAL ;
    PORT
      LAYER M5 ;
        RECT  34.512 0 34.536 0.084 ;
    END
  END b[184]
  PIN b[185]
    DIRECTION OUTPUT ;
    USE SIGNAL ;
    PORT
      LAYER M5 ;
        RECT  34.608 0 34.632 0.084 ;
    END
  END b[185]
  PIN b[186]
    DIRECTION OUTPUT ;
    USE SIGNAL ;
    PORT
      LAYER M5 ;
        RECT  34.704 0 34.728 0.084 ;
    END
  END b[186]
  PIN b[187]
    DIRECTION OUTPUT ;
    USE SIGNAL ;
    PORT
      LAYER M5 ;
        RECT  34.8 0 34.824 0.084 ;
    END
  END b[187]
  PIN b[188]
    DIRECTION OUTPUT ;
    USE SIGNAL ;
    PORT
      LAYER M5 ;
        RECT  34.896 0 34.92 0.084 ;
    END
  END b[188]
  PIN b[189]
    DIRECTION OUTPUT ;
    USE SIGNAL ;
    PORT
      LAYER M5 ;
        RECT  34.992 0 35.016 0.084 ;
    END
  END b[189]
  PIN b[18]
    DIRECTION OUTPUT ;
    USE SIGNAL ;
    PORT
      LAYER M5 ;
        RECT  30.864 0 30.888 0.084 ;
    END
  END b[18]
  PIN b[190]
    DIRECTION OUTPUT ;
    USE SIGNAL ;
    PORT
      LAYER M5 ;
        RECT  35.088 0 35.112 0.084 ;
    END
  END b[190]
  PIN b[191]
    DIRECTION OUTPUT ;
    USE SIGNAL ;
    PORT
      LAYER M5 ;
        RECT  35.184 0 35.208 0.084 ;
    END
  END b[191]
  PIN b[192]
    DIRECTION OUTPUT ;
    USE SIGNAL ;
    PORT
      LAYER M3 ;
        RECT  21.852 0 21.87 0.037 ;
    END
  END b[192]
  PIN b[193]
    DIRECTION OUTPUT ;
    USE SIGNAL ;
    PORT
      LAYER M3 ;
        RECT  21.924 0 21.942 0.037 ;
    END
  END b[193]
  PIN b[194]
    DIRECTION OUTPUT ;
    USE SIGNAL ;
    PORT
      LAYER M3 ;
        RECT  21.996 0 22.014 0.037 ;
    END
  END b[194]
  PIN b[195]
    DIRECTION OUTPUT ;
    USE SIGNAL ;
    PORT
      LAYER M3 ;
        RECT  22.068 0 22.086 0.037 ;
    END
  END b[195]
  PIN b[196]
    DIRECTION OUTPUT ;
    USE SIGNAL ;
    PORT
      LAYER M3 ;
        RECT  22.14 0 22.158 0.037 ;
    END
  END b[196]
  PIN b[197]
    DIRECTION OUTPUT ;
    USE SIGNAL ;
    PORT
      LAYER M3 ;
        RECT  22.212 0 22.23 0.037 ;
    END
  END b[197]
  PIN b[198]
    DIRECTION OUTPUT ;
    USE SIGNAL ;
    PORT
      LAYER M3 ;
        RECT  22.284 0 22.302 0.037 ;
    END
  END b[198]
  PIN b[199]
    DIRECTION OUTPUT ;
    USE SIGNAL ;
    PORT
      LAYER M3 ;
        RECT  22.356 0 22.374 0.037 ;
    END
  END b[199]
  PIN b[19]
    DIRECTION OUTPUT ;
    USE SIGNAL ;
    PORT
      LAYER M5 ;
        RECT  30.96 0 30.984 0.084 ;
    END
  END b[19]
  PIN b[1]
    DIRECTION OUTPUT ;
    USE SIGNAL ;
    PORT
      LAYER M5 ;
        RECT  29.232 0 29.256 0.084 ;
    END
  END b[1]
  PIN b[200]
    DIRECTION OUTPUT ;
    USE SIGNAL ;
    PORT
      LAYER M3 ;
        RECT  22.428 0 22.446 0.037 ;
    END
  END b[200]
  PIN b[201]
    DIRECTION OUTPUT ;
    USE SIGNAL ;
    PORT
      LAYER M3 ;
        RECT  22.5 0 22.518 0.037 ;
    END
  END b[201]
  PIN b[202]
    DIRECTION OUTPUT ;
    USE SIGNAL ;
    PORT
      LAYER M3 ;
        RECT  22.572 0 22.59 0.037 ;
    END
  END b[202]
  PIN b[203]
    DIRECTION OUTPUT ;
    USE SIGNAL ;
    PORT
      LAYER M3 ;
        RECT  22.644 0 22.662 0.037 ;
    END
  END b[203]
  PIN b[204]
    DIRECTION OUTPUT ;
    USE SIGNAL ;
    PORT
      LAYER M3 ;
        RECT  22.716 0 22.734 0.037 ;
    END
  END b[204]
  PIN b[205]
    DIRECTION OUTPUT ;
    USE SIGNAL ;
    PORT
      LAYER M3 ;
        RECT  22.788 0 22.806 0.037 ;
    END
  END b[205]
  PIN b[206]
    DIRECTION OUTPUT ;
    USE SIGNAL ;
    PORT
      LAYER M3 ;
        RECT  22.86 0 22.878 0.037 ;
    END
  END b[206]
  PIN b[207]
    DIRECTION OUTPUT ;
    USE SIGNAL ;
    PORT
      LAYER M3 ;
        RECT  22.932 0 22.95 0.037 ;
    END
  END b[207]
  PIN b[208]
    DIRECTION OUTPUT ;
    USE SIGNAL ;
    PORT
      LAYER M3 ;
        RECT  23.004 0 23.022 0.037 ;
    END
  END b[208]
  PIN b[209]
    DIRECTION OUTPUT ;
    USE SIGNAL ;
    PORT
      LAYER M3 ;
        RECT  23.076 0 23.094 0.037 ;
    END
  END b[209]
  PIN b[20]
    DIRECTION OUTPUT ;
    USE SIGNAL ;
    PORT
      LAYER M5 ;
        RECT  31.056 0 31.08 0.084 ;
    END
  END b[20]
  PIN b[210]
    DIRECTION OUTPUT ;
    USE SIGNAL ;
    PORT
      LAYER M3 ;
        RECT  23.148 0 23.166 0.037 ;
    END
  END b[210]
  PIN b[211]
    DIRECTION OUTPUT ;
    USE SIGNAL ;
    PORT
      LAYER M3 ;
        RECT  23.22 0 23.238 0.037 ;
    END
  END b[211]
  PIN b[212]
    DIRECTION OUTPUT ;
    USE SIGNAL ;
    PORT
      LAYER M3 ;
        RECT  23.292 0 23.31 0.037 ;
    END
  END b[212]
  PIN b[213]
    DIRECTION OUTPUT ;
    USE SIGNAL ;
    PORT
      LAYER M3 ;
        RECT  23.364 0 23.382 0.037 ;
    END
  END b[213]
  PIN b[214]
    DIRECTION OUTPUT ;
    USE SIGNAL ;
    PORT
      LAYER M3 ;
        RECT  23.436 0 23.454 0.037 ;
    END
  END b[214]
  PIN b[215]
    DIRECTION OUTPUT ;
    USE SIGNAL ;
    PORT
      LAYER M3 ;
        RECT  23.508 0 23.526 0.037 ;
    END
  END b[215]
  PIN b[216]
    DIRECTION OUTPUT ;
    USE SIGNAL ;
    PORT
      LAYER M3 ;
        RECT  23.58 0 23.598 0.037 ;
    END
  END b[216]
  PIN b[217]
    DIRECTION OUTPUT ;
    USE SIGNAL ;
    PORT
      LAYER M3 ;
        RECT  23.652 0 23.67 0.037 ;
    END
  END b[217]
  PIN b[218]
    DIRECTION OUTPUT ;
    USE SIGNAL ;
    PORT
      LAYER M3 ;
        RECT  23.724 0 23.742 0.037 ;
    END
  END b[218]
  PIN b[219]
    DIRECTION OUTPUT ;
    USE SIGNAL ;
    PORT
      LAYER M3 ;
        RECT  23.796 0 23.814 0.037 ;
    END
  END b[219]
  PIN b[21]
    DIRECTION OUTPUT ;
    USE SIGNAL ;
    PORT
      LAYER M5 ;
        RECT  31.152 0 31.176 0.084 ;
    END
  END b[21]
  PIN b[220]
    DIRECTION OUTPUT ;
    USE SIGNAL ;
    PORT
      LAYER M3 ;
        RECT  23.868 0 23.886 0.037 ;
    END
  END b[220]
  PIN b[221]
    DIRECTION OUTPUT ;
    USE SIGNAL ;
    PORT
      LAYER M3 ;
        RECT  23.94 0 23.958 0.037 ;
    END
  END b[221]
  PIN b[222]
    DIRECTION OUTPUT ;
    USE SIGNAL ;
    PORT
      LAYER M3 ;
        RECT  24.012 0 24.03 0.037 ;
    END
  END b[222]
  PIN b[223]
    DIRECTION OUTPUT ;
    USE SIGNAL ;
    PORT
      LAYER M3 ;
        RECT  24.084 0 24.102 0.037 ;
    END
  END b[223]
  PIN b[224]
    DIRECTION OUTPUT ;
    USE SIGNAL ;
    PORT
      LAYER M3 ;
        RECT  24.156 0 24.174 0.037 ;
    END
  END b[224]
  PIN b[225]
    DIRECTION OUTPUT ;
    USE SIGNAL ;
    PORT
      LAYER M3 ;
        RECT  24.228 0 24.246 0.037 ;
    END
  END b[225]
  PIN b[226]
    DIRECTION OUTPUT ;
    USE SIGNAL ;
    PORT
      LAYER M3 ;
        RECT  24.3 0 24.318 0.037 ;
    END
  END b[226]
  PIN b[227]
    DIRECTION OUTPUT ;
    USE SIGNAL ;
    PORT
      LAYER M3 ;
        RECT  24.372 0 24.39 0.037 ;
    END
  END b[227]
  PIN b[228]
    DIRECTION OUTPUT ;
    USE SIGNAL ;
    PORT
      LAYER M3 ;
        RECT  24.444 0 24.462 0.037 ;
    END
  END b[228]
  PIN b[229]
    DIRECTION OUTPUT ;
    USE SIGNAL ;
    PORT
      LAYER M3 ;
        RECT  24.516 0 24.534 0.037 ;
    END
  END b[229]
  PIN b[22]
    DIRECTION OUTPUT ;
    USE SIGNAL ;
    PORT
      LAYER M5 ;
        RECT  31.248 0 31.272 0.084 ;
    END
  END b[22]
  PIN b[230]
    DIRECTION OUTPUT ;
    USE SIGNAL ;
    PORT
      LAYER M3 ;
        RECT  24.588 0 24.606 0.037 ;
    END
  END b[230]
  PIN b[231]
    DIRECTION OUTPUT ;
    USE SIGNAL ;
    PORT
      LAYER M3 ;
        RECT  24.66 0 24.678 0.037 ;
    END
  END b[231]
  PIN b[232]
    DIRECTION OUTPUT ;
    USE SIGNAL ;
    PORT
      LAYER M3 ;
        RECT  24.732 0 24.75 0.037 ;
    END
  END b[232]
  PIN b[233]
    DIRECTION OUTPUT ;
    USE SIGNAL ;
    PORT
      LAYER M3 ;
        RECT  24.804 0 24.822 0.037 ;
    END
  END b[233]
  PIN b[234]
    DIRECTION OUTPUT ;
    USE SIGNAL ;
    PORT
      LAYER M3 ;
        RECT  24.876 0 24.894 0.037 ;
    END
  END b[234]
  PIN b[235]
    DIRECTION OUTPUT ;
    USE SIGNAL ;
    PORT
      LAYER M3 ;
        RECT  24.948 0 24.966 0.037 ;
    END
  END b[235]
  PIN b[236]
    DIRECTION OUTPUT ;
    USE SIGNAL ;
    PORT
      LAYER M3 ;
        RECT  25.02 0 25.038 0.037 ;
    END
  END b[236]
  PIN b[237]
    DIRECTION OUTPUT ;
    USE SIGNAL ;
    PORT
      LAYER M3 ;
        RECT  25.092 0 25.11 0.037 ;
    END
  END b[237]
  PIN b[238]
    DIRECTION OUTPUT ;
    USE SIGNAL ;
    PORT
      LAYER M3 ;
        RECT  25.164 0 25.182 0.037 ;
    END
  END b[238]
  PIN b[239]
    DIRECTION OUTPUT ;
    USE SIGNAL ;
    PORT
      LAYER M3 ;
        RECT  25.236 0 25.254 0.037 ;
    END
  END b[239]
  PIN b[23]
    DIRECTION OUTPUT ;
    USE SIGNAL ;
    PORT
      LAYER M5 ;
        RECT  31.344 0 31.368 0.084 ;
    END
  END b[23]
  PIN b[240]
    DIRECTION OUTPUT ;
    USE SIGNAL ;
    PORT
      LAYER M3 ;
        RECT  25.308 0 25.326 0.037 ;
    END
  END b[240]
  PIN b[241]
    DIRECTION OUTPUT ;
    USE SIGNAL ;
    PORT
      LAYER M3 ;
        RECT  25.38 0 25.398 0.037 ;
    END
  END b[241]
  PIN b[242]
    DIRECTION OUTPUT ;
    USE SIGNAL ;
    PORT
      LAYER M3 ;
        RECT  25.452 0 25.47 0.037 ;
    END
  END b[242]
  PIN b[243]
    DIRECTION OUTPUT ;
    USE SIGNAL ;
    PORT
      LAYER M3 ;
        RECT  25.524 0 25.542 0.037 ;
    END
  END b[243]
  PIN b[244]
    DIRECTION OUTPUT ;
    USE SIGNAL ;
    PORT
      LAYER M3 ;
        RECT  25.596 0 25.614 0.037 ;
    END
  END b[244]
  PIN b[245]
    DIRECTION OUTPUT ;
    USE SIGNAL ;
    PORT
      LAYER M3 ;
        RECT  25.668 0 25.686 0.037 ;
    END
  END b[245]
  PIN b[246]
    DIRECTION OUTPUT ;
    USE SIGNAL ;
    PORT
      LAYER M3 ;
        RECT  25.74 0 25.758 0.037 ;
    END
  END b[246]
  PIN b[247]
    DIRECTION OUTPUT ;
    USE SIGNAL ;
    PORT
      LAYER M3 ;
        RECT  25.812 0 25.83 0.037 ;
    END
  END b[247]
  PIN b[248]
    DIRECTION OUTPUT ;
    USE SIGNAL ;
    PORT
      LAYER M3 ;
        RECT  25.884 0 25.902 0.037 ;
    END
  END b[248]
  PIN b[249]
    DIRECTION OUTPUT ;
    USE SIGNAL ;
    PORT
      LAYER M3 ;
        RECT  25.956 0 25.974 0.037 ;
    END
  END b[249]
  PIN b[24]
    DIRECTION OUTPUT ;
    USE SIGNAL ;
    PORT
      LAYER M5 ;
        RECT  31.44 0 31.464 0.084 ;
    END
  END b[24]
  PIN b[250]
    DIRECTION OUTPUT ;
    USE SIGNAL ;
    PORT
      LAYER M3 ;
        RECT  26.028 0 26.046 0.037 ;
    END
  END b[250]
  PIN b[251]
    DIRECTION OUTPUT ;
    USE SIGNAL ;
    PORT
      LAYER M3 ;
        RECT  26.1 0 26.118 0.037 ;
    END
  END b[251]
  PIN b[252]
    DIRECTION OUTPUT ;
    USE SIGNAL ;
    PORT
      LAYER M3 ;
        RECT  26.172 0 26.19 0.037 ;
    END
  END b[252]
  PIN b[253]
    DIRECTION OUTPUT ;
    USE SIGNAL ;
    PORT
      LAYER M3 ;
        RECT  26.244 0 26.262 0.037 ;
    END
  END b[253]
  PIN b[254]
    DIRECTION OUTPUT ;
    USE SIGNAL ;
    PORT
      LAYER M3 ;
        RECT  26.316 0 26.334 0.037 ;
    END
  END b[254]
  PIN b[255]
    DIRECTION OUTPUT ;
    USE SIGNAL ;
    PORT
      LAYER M3 ;
        RECT  26.388 0 26.406 0.037 ;
    END
  END b[255]
  PIN b[256]
    DIRECTION OUTPUT ;
    USE SIGNAL ;
    PORT
      LAYER M3 ;
        RECT  26.46 0 26.478 0.037 ;
    END
  END b[256]
  PIN b[257]
    DIRECTION OUTPUT ;
    USE SIGNAL ;
    PORT
      LAYER M3 ;
        RECT  26.532 0 26.55 0.037 ;
    END
  END b[257]
  PIN b[258]
    DIRECTION OUTPUT ;
    USE SIGNAL ;
    PORT
      LAYER M3 ;
        RECT  26.604 0 26.622 0.037 ;
    END
  END b[258]
  PIN b[259]
    DIRECTION OUTPUT ;
    USE SIGNAL ;
    PORT
      LAYER M3 ;
        RECT  26.676 0 26.694 0.037 ;
    END
  END b[259]
  PIN b[25]
    DIRECTION OUTPUT ;
    USE SIGNAL ;
    PORT
      LAYER M5 ;
        RECT  31.536 0 31.56 0.084 ;
    END
  END b[25]
  PIN b[260]
    DIRECTION OUTPUT ;
    USE SIGNAL ;
    PORT
      LAYER M3 ;
        RECT  26.748 0 26.766 0.037 ;
    END
  END b[260]
  PIN b[261]
    DIRECTION OUTPUT ;
    USE SIGNAL ;
    PORT
      LAYER M3 ;
        RECT  26.82 0 26.838 0.037 ;
    END
  END b[261]
  PIN b[262]
    DIRECTION OUTPUT ;
    USE SIGNAL ;
    PORT
      LAYER M3 ;
        RECT  26.892 0 26.91 0.037 ;
    END
  END b[262]
  PIN b[263]
    DIRECTION OUTPUT ;
    USE SIGNAL ;
    PORT
      LAYER M3 ;
        RECT  26.964 0 26.982 0.037 ;
    END
  END b[263]
  PIN b[264]
    DIRECTION OUTPUT ;
    USE SIGNAL ;
    PORT
      LAYER M3 ;
        RECT  27.036 0 27.054 0.037 ;
    END
  END b[264]
  PIN b[265]
    DIRECTION OUTPUT ;
    USE SIGNAL ;
    PORT
      LAYER M3 ;
        RECT  27.108 0 27.126 0.037 ;
    END
  END b[265]
  PIN b[266]
    DIRECTION OUTPUT ;
    USE SIGNAL ;
    PORT
      LAYER M3 ;
        RECT  27.18 0 27.198 0.037 ;
    END
  END b[266]
  PIN b[267]
    DIRECTION OUTPUT ;
    USE SIGNAL ;
    PORT
      LAYER M3 ;
        RECT  27.252 0 27.27 0.037 ;
    END
  END b[267]
  PIN b[268]
    DIRECTION OUTPUT ;
    USE SIGNAL ;
    PORT
      LAYER M3 ;
        RECT  27.324 0 27.342 0.037 ;
    END
  END b[268]
  PIN b[269]
    DIRECTION OUTPUT ;
    USE SIGNAL ;
    PORT
      LAYER M3 ;
        RECT  27.396 0 27.414 0.037 ;
    END
  END b[269]
  PIN b[26]
    DIRECTION OUTPUT ;
    USE SIGNAL ;
    PORT
      LAYER M5 ;
        RECT  31.632 0 31.656 0.084 ;
    END
  END b[26]
  PIN b[270]
    DIRECTION OUTPUT ;
    USE SIGNAL ;
    PORT
      LAYER M3 ;
        RECT  27.468 0 27.486 0.037 ;
    END
  END b[270]
  PIN b[271]
    DIRECTION OUTPUT ;
    USE SIGNAL ;
    PORT
      LAYER M3 ;
        RECT  27.54 0 27.558 0.037 ;
    END
  END b[271]
  PIN b[27]
    DIRECTION OUTPUT ;
    USE SIGNAL ;
    PORT
      LAYER M5 ;
        RECT  31.728 0 31.752 0.084 ;
    END
  END b[27]
  PIN b[28]
    DIRECTION OUTPUT ;
    USE SIGNAL ;
    PORT
      LAYER M5 ;
        RECT  31.824 0 31.848 0.084 ;
    END
  END b[28]
  PIN b[29]
    DIRECTION OUTPUT ;
    USE SIGNAL ;
    PORT
      LAYER M5 ;
        RECT  31.92 0 31.944 0.084 ;
    END
  END b[29]
  PIN b[2]
    DIRECTION OUTPUT ;
    USE SIGNAL ;
    PORT
      LAYER M5 ;
        RECT  29.328 0 29.352 0.084 ;
    END
  END b[2]
  PIN b[30]
    DIRECTION OUTPUT ;
    USE SIGNAL ;
    PORT
      LAYER M5 ;
        RECT  32.016 0 32.04 0.084 ;
    END
  END b[30]
  PIN b[31]
    DIRECTION OUTPUT ;
    USE SIGNAL ;
    PORT
      LAYER M5 ;
        RECT  32.112 0 32.136 0.084 ;
    END
  END b[31]
  PIN b[32]
    DIRECTION OUTPUT ;
    USE SIGNAL ;
    PORT
      LAYER M5 ;
        RECT  35.28 0 35.304 0.084 ;
    END
  END b[32]
  PIN b[33]
    DIRECTION OUTPUT ;
    USE SIGNAL ;
    PORT
      LAYER M5 ;
        RECT  35.376 0 35.4 0.084 ;
    END
  END b[33]
  PIN b[34]
    DIRECTION OUTPUT ;
    USE SIGNAL ;
    PORT
      LAYER M5 ;
        RECT  35.472 0 35.496 0.084 ;
    END
  END b[34]
  PIN b[35]
    DIRECTION OUTPUT ;
    USE SIGNAL ;
    PORT
      LAYER M5 ;
        RECT  35.568 0 35.592 0.084 ;
    END
  END b[35]
  PIN b[36]
    DIRECTION OUTPUT ;
    USE SIGNAL ;
    PORT
      LAYER M5 ;
        RECT  35.664 0 35.688 0.084 ;
    END
  END b[36]
  PIN b[37]
    DIRECTION OUTPUT ;
    USE SIGNAL ;
    PORT
      LAYER M5 ;
        RECT  35.76 0 35.784 0.084 ;
    END
  END b[37]
  PIN b[38]
    DIRECTION OUTPUT ;
    USE SIGNAL ;
    PORT
      LAYER M5 ;
        RECT  35.856 0 35.88 0.084 ;
    END
  END b[38]
  PIN b[39]
    DIRECTION OUTPUT ;
    USE SIGNAL ;
    PORT
      LAYER M5 ;
        RECT  35.952 0 35.976 0.084 ;
    END
  END b[39]
  PIN b[3]
    DIRECTION OUTPUT ;
    USE SIGNAL ;
    PORT
      LAYER M5 ;
        RECT  29.424 0 29.448 0.084 ;
    END
  END b[3]
  PIN b[40]
    DIRECTION OUTPUT ;
    USE SIGNAL ;
    PORT
      LAYER M5 ;
        RECT  36.048 0 36.072 0.084 ;
    END
  END b[40]
  PIN b[41]
    DIRECTION OUTPUT ;
    USE SIGNAL ;
    PORT
      LAYER M5 ;
        RECT  36.144 0 36.168 0.084 ;
    END
  END b[41]
  PIN b[42]
    DIRECTION OUTPUT ;
    USE SIGNAL ;
    PORT
      LAYER M5 ;
        RECT  36.24 0 36.264 0.084 ;
    END
  END b[42]
  PIN b[43]
    DIRECTION OUTPUT ;
    USE SIGNAL ;
    PORT
      LAYER M5 ;
        RECT  36.336 0 36.36 0.084 ;
    END
  END b[43]
  PIN b[44]
    DIRECTION OUTPUT ;
    USE SIGNAL ;
    PORT
      LAYER M5 ;
        RECT  36.432 0 36.456 0.084 ;
    END
  END b[44]
  PIN b[45]
    DIRECTION OUTPUT ;
    USE SIGNAL ;
    PORT
      LAYER M5 ;
        RECT  36.528 0 36.552 0.084 ;
    END
  END b[45]
  PIN b[46]
    DIRECTION OUTPUT ;
    USE SIGNAL ;
    PORT
      LAYER M5 ;
        RECT  36.624 0 36.648 0.084 ;
    END
  END b[46]
  PIN b[47]
    DIRECTION OUTPUT ;
    USE SIGNAL ;
    PORT
      LAYER M5 ;
        RECT  36.72 0 36.744 0.084 ;
    END
  END b[47]
  PIN b[48]
    DIRECTION OUTPUT ;
    USE SIGNAL ;
    PORT
      LAYER M5 ;
        RECT  36.816 0 36.84 0.084 ;
    END
  END b[48]
  PIN b[49]
    DIRECTION OUTPUT ;
    USE SIGNAL ;
    PORT
      LAYER M5 ;
        RECT  36.912 0 36.936 0.084 ;
    END
  END b[49]
  PIN b[4]
    DIRECTION OUTPUT ;
    USE SIGNAL ;
    PORT
      LAYER M5 ;
        RECT  29.52 0 29.544 0.084 ;
    END
  END b[4]
  PIN b[50]
    DIRECTION OUTPUT ;
    USE SIGNAL ;
    PORT
      LAYER M5 ;
        RECT  37.008 0 37.032 0.084 ;
    END
  END b[50]
  PIN b[51]
    DIRECTION OUTPUT ;
    USE SIGNAL ;
    PORT
      LAYER M5 ;
        RECT  37.104 0 37.128 0.084 ;
    END
  END b[51]
  PIN b[52]
    DIRECTION OUTPUT ;
    USE SIGNAL ;
    PORT
      LAYER M5 ;
        RECT  37.2 0 37.224 0.084 ;
    END
  END b[52]
  PIN b[53]
    DIRECTION OUTPUT ;
    USE SIGNAL ;
    PORT
      LAYER M5 ;
        RECT  37.296 0 37.32 0.084 ;
    END
  END b[53]
  PIN b[54]
    DIRECTION OUTPUT ;
    USE SIGNAL ;
    PORT
      LAYER M5 ;
        RECT  37.392 0 37.416 0.084 ;
    END
  END b[54]
  PIN b[55]
    DIRECTION OUTPUT ;
    USE SIGNAL ;
    PORT
      LAYER M5 ;
        RECT  37.488 0 37.512 0.084 ;
    END
  END b[55]
  PIN b[56]
    DIRECTION OUTPUT ;
    USE SIGNAL ;
    PORT
      LAYER M5 ;
        RECT  37.584 0 37.608 0.084 ;
    END
  END b[56]
  PIN b[57]
    DIRECTION OUTPUT ;
    USE SIGNAL ;
    PORT
      LAYER M5 ;
        RECT  37.68 0 37.704 0.084 ;
    END
  END b[57]
  PIN b[58]
    DIRECTION OUTPUT ;
    USE SIGNAL ;
    PORT
      LAYER M5 ;
        RECT  37.776 0 37.8 0.084 ;
    END
  END b[58]
  PIN b[59]
    DIRECTION OUTPUT ;
    USE SIGNAL ;
    PORT
      LAYER M5 ;
        RECT  37.872 0 37.896 0.084 ;
    END
  END b[59]
  PIN b[5]
    DIRECTION OUTPUT ;
    USE SIGNAL ;
    PORT
      LAYER M5 ;
        RECT  29.616 0 29.64 0.084 ;
    END
  END b[5]
  PIN b[60]
    DIRECTION OUTPUT ;
    USE SIGNAL ;
    PORT
      LAYER M5 ;
        RECT  37.968 0 37.992 0.084 ;
    END
  END b[60]
  PIN b[61]
    DIRECTION OUTPUT ;
    USE SIGNAL ;
    PORT
      LAYER M5 ;
        RECT  38.064 0 38.088 0.084 ;
    END
  END b[61]
  PIN b[62]
    DIRECTION OUTPUT ;
    USE SIGNAL ;
    PORT
      LAYER M5 ;
        RECT  38.16 0 38.184 0.084 ;
    END
  END b[62]
  PIN b[63]
    DIRECTION OUTPUT ;
    USE SIGNAL ;
    PORT
      LAYER M5 ;
        RECT  38.256 0 38.28 0.084 ;
    END
  END b[63]
  PIN b[64]
    DIRECTION OUTPUT ;
    USE SIGNAL ;
    PORT
      LAYER M5 ;
        RECT  22.992 0 23.016 0.084 ;
    END
  END b[64]
  PIN b[65]
    DIRECTION OUTPUT ;
    USE SIGNAL ;
    PORT
      LAYER M5 ;
        RECT  23.088 0 23.112 0.084 ;
    END
  END b[65]
  PIN b[66]
    DIRECTION OUTPUT ;
    USE SIGNAL ;
    PORT
      LAYER M5 ;
        RECT  23.184 0 23.208 0.084 ;
    END
  END b[66]
  PIN b[67]
    DIRECTION OUTPUT ;
    USE SIGNAL ;
    PORT
      LAYER M5 ;
        RECT  23.28 0 23.304 0.084 ;
    END
  END b[67]
  PIN b[68]
    DIRECTION OUTPUT ;
    USE SIGNAL ;
    PORT
      LAYER M5 ;
        RECT  23.376 0 23.4 0.084 ;
    END
  END b[68]
  PIN b[69]
    DIRECTION OUTPUT ;
    USE SIGNAL ;
    PORT
      LAYER M5 ;
        RECT  23.472 0 23.496 0.084 ;
    END
  END b[69]
  PIN b[6]
    DIRECTION OUTPUT ;
    USE SIGNAL ;
    PORT
      LAYER M5 ;
        RECT  29.712 0 29.736 0.084 ;
    END
  END b[6]
  PIN b[70]
    DIRECTION OUTPUT ;
    USE SIGNAL ;
    PORT
      LAYER M5 ;
        RECT  23.568 0 23.592 0.084 ;
    END
  END b[70]
  PIN b[71]
    DIRECTION OUTPUT ;
    USE SIGNAL ;
    PORT
      LAYER M5 ;
        RECT  23.664 0 23.688 0.084 ;
    END
  END b[71]
  PIN b[72]
    DIRECTION OUTPUT ;
    USE SIGNAL ;
    PORT
      LAYER M5 ;
        RECT  23.76 0 23.784 0.084 ;
    END
  END b[72]
  PIN b[73]
    DIRECTION OUTPUT ;
    USE SIGNAL ;
    PORT
      LAYER M5 ;
        RECT  23.856 0 23.88 0.084 ;
    END
  END b[73]
  PIN b[74]
    DIRECTION OUTPUT ;
    USE SIGNAL ;
    PORT
      LAYER M5 ;
        RECT  23.952 0 23.976 0.084 ;
    END
  END b[74]
  PIN b[75]
    DIRECTION OUTPUT ;
    USE SIGNAL ;
    PORT
      LAYER M5 ;
        RECT  24.048 0 24.072 0.084 ;
    END
  END b[75]
  PIN b[76]
    DIRECTION OUTPUT ;
    USE SIGNAL ;
    PORT
      LAYER M5 ;
        RECT  24.144 0 24.168 0.084 ;
    END
  END b[76]
  PIN b[77]
    DIRECTION OUTPUT ;
    USE SIGNAL ;
    PORT
      LAYER M5 ;
        RECT  24.24 0 24.264 0.084 ;
    END
  END b[77]
  PIN b[78]
    DIRECTION OUTPUT ;
    USE SIGNAL ;
    PORT
      LAYER M5 ;
        RECT  24.336 0 24.36 0.084 ;
    END
  END b[78]
  PIN b[79]
    DIRECTION OUTPUT ;
    USE SIGNAL ;
    PORT
      LAYER M5 ;
        RECT  24.432 0 24.456 0.084 ;
    END
  END b[79]
  PIN b[7]
    DIRECTION OUTPUT ;
    USE SIGNAL ;
    PORT
      LAYER M5 ;
        RECT  29.808 0 29.832 0.084 ;
    END
  END b[7]
  PIN b[80]
    DIRECTION OUTPUT ;
    USE SIGNAL ;
    PORT
      LAYER M5 ;
        RECT  24.528 0 24.552 0.084 ;
    END
  END b[80]
  PIN b[81]
    DIRECTION OUTPUT ;
    USE SIGNAL ;
    PORT
      LAYER M5 ;
        RECT  24.624 0 24.648 0.084 ;
    END
  END b[81]
  PIN b[82]
    DIRECTION OUTPUT ;
    USE SIGNAL ;
    PORT
      LAYER M5 ;
        RECT  24.72 0 24.744 0.084 ;
    END
  END b[82]
  PIN b[83]
    DIRECTION OUTPUT ;
    USE SIGNAL ;
    PORT
      LAYER M5 ;
        RECT  24.816 0 24.84 0.084 ;
    END
  END b[83]
  PIN b[84]
    DIRECTION OUTPUT ;
    USE SIGNAL ;
    PORT
      LAYER M5 ;
        RECT  24.912 0 24.936 0.084 ;
    END
  END b[84]
  PIN b[85]
    DIRECTION OUTPUT ;
    USE SIGNAL ;
    PORT
      LAYER M5 ;
        RECT  25.008 0 25.032 0.084 ;
    END
  END b[85]
  PIN b[86]
    DIRECTION OUTPUT ;
    USE SIGNAL ;
    PORT
      LAYER M5 ;
        RECT  25.104 0 25.128 0.084 ;
    END
  END b[86]
  PIN b[87]
    DIRECTION OUTPUT ;
    USE SIGNAL ;
    PORT
      LAYER M5 ;
        RECT  25.2 0 25.224 0.084 ;
    END
  END b[87]
  PIN b[88]
    DIRECTION OUTPUT ;
    USE SIGNAL ;
    PORT
      LAYER M5 ;
        RECT  25.296 0 25.32 0.084 ;
    END
  END b[88]
  PIN b[89]
    DIRECTION OUTPUT ;
    USE SIGNAL ;
    PORT
      LAYER M5 ;
        RECT  25.392 0 25.416 0.084 ;
    END
  END b[89]
  PIN b[8]
    DIRECTION OUTPUT ;
    USE SIGNAL ;
    PORT
      LAYER M5 ;
        RECT  29.904 0 29.928 0.084 ;
    END
  END b[8]
  PIN b[90]
    DIRECTION OUTPUT ;
    USE SIGNAL ;
    PORT
      LAYER M5 ;
        RECT  25.488 0 25.512 0.084 ;
    END
  END b[90]
  PIN b[91]
    DIRECTION OUTPUT ;
    USE SIGNAL ;
    PORT
      LAYER M5 ;
        RECT  25.584 0 25.608 0.084 ;
    END
  END b[91]
  PIN b[92]
    DIRECTION OUTPUT ;
    USE SIGNAL ;
    PORT
      LAYER M5 ;
        RECT  25.68 0 25.704 0.084 ;
    END
  END b[92]
  PIN b[93]
    DIRECTION OUTPUT ;
    USE SIGNAL ;
    PORT
      LAYER M5 ;
        RECT  25.776 0 25.8 0.084 ;
    END
  END b[93]
  PIN b[94]
    DIRECTION OUTPUT ;
    USE SIGNAL ;
    PORT
      LAYER M5 ;
        RECT  25.872 0 25.896 0.084 ;
    END
  END b[94]
  PIN b[95]
    DIRECTION OUTPUT ;
    USE SIGNAL ;
    PORT
      LAYER M5 ;
        RECT  25.968 0 25.992 0.084 ;
    END
  END b[95]
  PIN b[96]
    DIRECTION OUTPUT ;
    USE SIGNAL ;
    PORT
      LAYER M5 ;
        RECT  19.92 0 19.944 0.084 ;
    END
  END b[96]
  PIN b[97]
    DIRECTION OUTPUT ;
    USE SIGNAL ;
    PORT
      LAYER M5 ;
        RECT  20.016 0 20.04 0.084 ;
    END
  END b[97]
  PIN b[98]
    DIRECTION OUTPUT ;
    USE SIGNAL ;
    PORT
      LAYER M5 ;
        RECT  20.112 0 20.136 0.084 ;
    END
  END b[98]
  PIN b[99]
    DIRECTION OUTPUT ;
    USE SIGNAL ;
    PORT
      LAYER M5 ;
        RECT  20.208 0 20.232 0.084 ;
    END
  END b[99]
  PIN b[9]
    DIRECTION OUTPUT ;
    USE SIGNAL ;
    PORT
      LAYER M5 ;
        RECT  30 0 30.024 0.084 ;
    END
  END b[9]
  PIN ck_o[0]
    DIRECTION OUTPUT ;
    USE SIGNAL ;
    PORT
      LAYER M3 ;
        RECT  27.612 0 27.63 0.037 ;
    END
  END ck_o[0]
  PIN ck_o[1]
    DIRECTION OUTPUT ;
    USE SIGNAL ;
    PORT
      LAYER M3 ;
        RECT  27.684 0 27.702 0.037 ;
    END
  END ck_o[1]
  PIN ckf
    DIRECTION INPUT ;
    USE SIGNAL ;
    PORT
      LAYER M5 ;
        RECT  30.864 21.516 30.888 21.6 ;
    END
  END ckf
  PIN ea
    DIRECTION INPUT ;
    USE SIGNAL ;
    PORT
      LAYER M5 ;
        RECT  30.96 21.516 30.984 21.6 ;
    END
  END ea
  PIN eb[0]
    DIRECTION OUTPUT ;
    USE SIGNAL ;
    PORT
      LAYER M3 ;
        RECT  27.756 0 27.774 0.037 ;
    END
  END eb[0]
  PIN eb[1]
    DIRECTION OUTPUT ;
    USE SIGNAL ;
    PORT
      LAYER M3 ;
        RECT  27.828 0 27.846 0.037 ;
    END
  END eb[1]
  PIN VDD
    DIRECTION INOUT ;
    USE POWER ;
    PORT
      LAYER M5 ;
        RECT  51.192 2.151 51.312 19.449 ;
        RECT  48.492 2.151 48.612 19.449 ;
        RECT  45.792 2.151 45.912 19.449 ;
        RECT  43.092 2.151 43.212 19.449 ;
        RECT  40.392 2.151 40.512 19.449 ;
        RECT  37.692 2.151 37.812 19.449 ;
        RECT  34.992 2.151 35.112 19.449 ;
        RECT  32.292 2.151 32.412 19.449 ;
        RECT  29.592 2.151 29.712 19.449 ;
        RECT  26.892 2.151 27.012 19.449 ;
        RECT  24.192 2.151 24.312 19.449 ;
        RECT  21.492 2.151 21.612 19.449 ;
        RECT  18.792 2.151 18.912 19.449 ;
        RECT  16.092 2.151 16.212 19.449 ;
        RECT  13.392 2.151 13.512 19.449 ;
        RECT  10.692 2.151 10.812 19.449 ;
        RECT  7.992 2.151 8.112 19.449 ;
        RECT  5.292 2.151 5.412 19.449 ;
        RECT  2.592 2.151 2.712 19.449 ;
    END
  END VDD
  PIN VSS
    DIRECTION INOUT ;
    USE GROUND ;
    PORT
      LAYER M5 ;
        RECT  51 2.137 51.12 19.463 ;
        RECT  48.3 2.137 48.42 19.463 ;
        RECT  45.6 2.137 45.72 19.463 ;
        RECT  42.9 2.137 43.02 19.463 ;
        RECT  40.2 2.137 40.32 19.463 ;
        RECT  37.5 2.137 37.62 19.463 ;
        RECT  34.8 2.137 34.92 19.463 ;
        RECT  32.1 2.137 32.22 19.463 ;
        RECT  29.4 2.137 29.52 19.463 ;
        RECT  26.7 2.137 26.82 19.463 ;
        RECT  24 2.137 24.12 19.463 ;
        RECT  21.3 2.137 21.42 19.463 ;
        RECT  18.6 2.137 18.72 19.463 ;
        RECT  15.9 2.137 16.02 19.463 ;
        RECT  13.2 2.137 13.32 19.463 ;
        RECT  10.5 2.137 10.62 19.463 ;
        RECT  7.8 2.137 7.92 19.463 ;
        RECT  5.1 2.137 5.22 19.463 ;
        RECT  2.4 2.137 2.52 19.463 ;
    END
  END VSS
  OBS
    LAYER RVTN ;
     RECT  2.16 2.16 51.84 2.295 ;
     RECT  2.16 2.565 51.84 2.835 ;
     RECT  2.16 3.105 51.84 3.375 ;
     RECT  2.16 3.645 51.84 3.915 ;
     RECT  2.16 4.185 51.84 4.455 ;
     RECT  2.16 4.725 51.84 4.995 ;
     RECT  2.16 5.265 51.84 5.535 ;
     RECT  2.16 5.805 51.84 6.075 ;
     RECT  2.16 6.345 51.84 6.615 ;
     RECT  2.16 6.885 51.84 7.155 ;
     RECT  2.16 7.425 51.84 7.695 ;
     RECT  2.16 7.965 51.84 8.235 ;
     RECT  2.16 8.505 51.84 8.775 ;
     RECT  2.16 9.045 51.84 9.315 ;
     RECT  2.16 9.585 51.84 9.855 ;
     RECT  2.16 10.125 51.84 10.395 ;
     RECT  2.16 10.665 51.84 10.935 ;
     RECT  2.16 11.205 51.84 11.475 ;
     RECT  2.16 11.745 51.84 12.015 ;
     RECT  2.16 12.285 51.84 12.555 ;
     RECT  2.16 12.825 51.84 13.095 ;
     RECT  2.16 13.365 51.84 13.635 ;
     RECT  2.16 13.905 51.84 14.175 ;
     RECT  2.16 14.445 51.84 14.715 ;
     RECT  2.16 14.985 51.84 15.255 ;
     RECT  2.16 15.525 51.84 15.795 ;
     RECT  2.16 16.065 51.84 16.335 ;
     RECT  2.16 16.605 51.84 16.875 ;
     RECT  2.16 17.145 51.84 17.415 ;
     RECT  2.16 17.685 51.84 17.955 ;
     RECT  2.16 18.225 51.84 18.495 ;
     RECT  2.16 18.765 51.84 19.035 ;
     RECT  2.16 19.305 51.84 19.44 ;
    LAYER RVTP ;
     RECT  2.16 2.295 51.84 2.565 ;
     RECT  2.16 2.835 51.84 3.105 ;
     RECT  2.16 3.375 51.84 3.645 ;
     RECT  2.16 3.915 51.84 4.185 ;
     RECT  2.16 4.455 51.84 4.725 ;
     RECT  2.16 4.995 51.84 5.265 ;
     RECT  2.16 5.535 51.84 5.805 ;
     RECT  2.16 6.075 51.84 6.345 ;
     RECT  2.16 6.615 51.84 6.885 ;
     RECT  2.16 7.155 51.84 7.425 ;
     RECT  2.16 7.695 51.84 7.965 ;
     RECT  2.16 8.235 51.84 8.505 ;
     RECT  2.16 8.775 51.84 9.045 ;
     RECT  2.16 9.315 51.84 9.585 ;
     RECT  2.16 9.855 51.84 10.125 ;
     RECT  2.16 10.395 51.84 10.665 ;
     RECT  2.16 10.935 51.84 11.205 ;
     RECT  2.16 11.475 51.84 11.745 ;
     RECT  2.16 12.015 51.84 12.285 ;
     RECT  2.16 12.555 51.84 12.825 ;
     RECT  2.16 13.095 51.84 13.365 ;
     RECT  2.16 13.635 51.84 13.905 ;
     RECT  2.16 14.175 51.84 14.445 ;
     RECT  2.16 14.715 51.84 14.985 ;
     RECT  2.16 15.255 51.84 15.525 ;
     RECT  2.16 15.795 51.84 16.065 ;
     RECT  2.16 16.335 51.84 16.605 ;
     RECT  2.16 16.875 51.84 17.145 ;
     RECT  2.16 17.415 51.84 17.685 ;
     RECT  2.16 17.955 51.84 18.225 ;
     RECT  2.16 18.495 51.84 18.765 ;
     RECT  2.16 19.035 51.84 19.305 ;
    LAYER M1 ;
     RECT  2.16 2.151 51.84 19.449 ;
    LAYER M2 ;
     RECT  2.16 2.151 19.903 19.449 ;
     RECT  19.903 2.106 20.227 19.449 ;
     RECT  20.227 2.034 20.371 19.449 ;
     RECT  20.371 1.836 21.847 19.449 ;
     RECT  21.847 0.144 21.919 0.162 ;
     RECT  21.919 0.072 22.099 0.162 ;
     RECT  22.099 0.036 22.135 0.162 ;
     RECT  21.847 1.8 22.135 19.449 ;
     RECT  22.135 1.728 23.179 19.449 ;
     RECT  23.179 1.152 23.351 19.449 ;
     RECT  22.135 0.036 23.467 0.198 ;
     RECT  23.467 0.036 24.295 0.234 ;
     RECT  23.351 1.728 24.367 19.449 ;
     RECT  24.367 1.224 24.403 19.449 ;
     RECT  24.295 0.036 24.503 0.279 ;
     RECT  24.503 0.036 24.791 0.198 ;
     RECT  24.403 1.152 25.079 19.449 ;
     RECT  25.231 21.474 25.339 21.492 ;
     RECT  25.339 21.474 25.475 21.564 ;
     RECT  24.791 0.036 25.627 0.162 ;
     RECT  25.627 0.036 25.987 0.594 ;
     RECT  25.079 1.728 25.987 19.449 ;
     RECT  25.987 1.728 26.051 19.494 ;
     RECT  26.239 21.546 26.275 21.564 ;
     RECT  26.051 1.926 26.455 19.494 ;
     RECT  25.987 0.036 26.527 0.738 ;
     RECT  26.527 0.036 26.627 0.819 ;
     RECT  26.275 21.474 26.771 21.564 ;
     RECT  26.771 21.51 27.095 21.564 ;
     RECT  27.095 21.546 27.167 21.564 ;
     RECT  26.627 0.036 27.347 0.324 ;
     RECT  27.347 0.036 27.599 0.198 ;
     RECT  26.455 1.926 27.743 19.989 ;
     RECT  27.599 0.036 27.887 0.162 ;
     RECT  27.743 1.926 28.003 19.494 ;
     RECT  27.887 0.036 29.399 0.126 ;
     RECT  29.399 0.036 29.759 0.09 ;
     RECT  29.759 0.036 30.515 0.054 ;
     RECT  28.003 1.836 30.551 19.494 ;
     RECT  30.551 1.836 30.775 19.449 ;
     RECT  30.775 1.8 30.811 19.449 ;
     RECT  30.811 1.764 33.331 19.449 ;
     RECT  33.331 1.728 36.887 19.449 ;
     RECT  36.887 1.881 37.859 19.449 ;
     RECT  37.859 2.151 51.84 19.449 ;
    LAYER M3 ;
     RECT  21.852 0.012 27.846 0.091 ;
     RECT  29.736 0.067 29.754 0.091 ;
     RECT  30.492 0.031 30.51 0.091 ;
     RECT  21.816 0.091 28.962 0.103 ;
     RECT  29.736 0.091 30.87 0.103 ;
     RECT  21.816 0.103 30.87 0.187 ;
     RECT  21.744 0.187 30.87 0.365 ;
     RECT  37.116 0.139 37.134 0.475 ;
     RECT  22.068 0.365 30.87 0.571 ;
     RECT  31.896 0.091 35.334 0.571 ;
     RECT  36.756 0.475 37.134 0.571 ;
     RECT  37.872 0.091 38.178 0.571 ;
     RECT  22.068 0.571 35.586 1.099 ;
     RECT  36.612 0.571 38.25 1.099 ;
     RECT  20.124 0.091 20.142 1.723 ;
     RECT  20.988 1.147 21.294 1.723 ;
     RECT  19.908 1.723 21.294 1.771 ;
     RECT  22.068 1.099 38.25 1.771 ;
     RECT  19.908 1.771 38.25 2.129 ;
     RECT  20.016 2.129 38.25 2.219 ;
     RECT  2.415 2.143 2.505 2.413 ;
     RECT  5.115 2.143 5.205 2.413 ;
     RECT  7.815 2.143 7.905 2.413 ;
     RECT  10.515 2.143 10.605 2.413 ;
     RECT  13.215 2.143 13.305 2.413 ;
     RECT  15.915 2.143 16.005 2.413 ;
     RECT  18.615 2.143 18.705 2.413 ;
     RECT  40.215 2.143 40.305 2.413 ;
     RECT  42.915 2.143 43.005 2.413 ;
     RECT  45.615 2.143 45.705 2.413 ;
     RECT  48.315 2.143 48.405 2.413 ;
     RECT  51.015 2.143 51.105 2.413 ;
     RECT  20.016 2.219 38.178 2.525 ;
     RECT  20.052 2.525 38.178 2.759 ;
     RECT  20.484 2.759 37.797 3.407 ;
     RECT  20.52 3.407 37.797 3.569 ;
     RECT  36.324 3.569 36.342 3.605 ;
     RECT  20.52 3.569 35.334 3.713 ;
     RECT  18.615 2.413 18.897 4.801 ;
     RECT  18.615 4.801 19.53 9.661 ;
     RECT  20.52 3.713 35.097 9.661 ;
     RECT  18.615 9.661 35.097 15.719 ;
     RECT  18.615 15.719 32.778 16.331 ;
     RECT  18.615 16.331 32.49 17.041 ;
     RECT  18.36 17.041 32.49 17.117 ;
     RECT  33.516 15.719 35.097 17.609 ;
     RECT  18.432 17.117 32.49 17.761 ;
     RECT  33.516 17.609 33.534 17.761 ;
     RECT  18.432 17.761 33.534 17.879 ;
     RECT  34.74 17.609 35.097 17.879 ;
     RECT  18.432 17.879 32.706 17.995 ;
     RECT  18.396 17.995 32.706 18.301 ;
     RECT  18.36 18.301 32.706 18.689 ;
     RECT  18.36 18.689 32.397 18.841 ;
     RECT  18.252 18.841 32.397 18.959 ;
     RECT  33.516 17.879 33.534 19.139 ;
     RECT  2.415 2.413 2.697 19.187 ;
     RECT  5.115 2.413 5.397 19.187 ;
     RECT  7.815 2.413 8.097 19.187 ;
     RECT  10.515 2.413 10.797 19.187 ;
     RECT  13.215 2.413 13.497 19.187 ;
     RECT  15.915 2.413 16.197 19.187 ;
     RECT  18.396 18.959 32.397 19.187 ;
     RECT  34.815 17.879 35.097 19.187 ;
     RECT  37.515 3.569 37.797 19.187 ;
     RECT  40.215 2.413 40.497 19.187 ;
     RECT  42.915 2.413 43.197 19.187 ;
     RECT  45.615 2.413 45.897 19.187 ;
     RECT  48.315 2.413 48.597 19.187 ;
     RECT  51.015 2.413 51.297 19.187 ;
     RECT  18.396 19.187 32.205 19.277 ;
     RECT  18.396 19.277 31.374 19.373 ;
     RECT  18.396 19.373 22.806 19.379 ;
     RECT  2.415 19.187 2.505 19.457 ;
     RECT  5.115 19.187 5.205 19.457 ;
     RECT  7.815 19.187 7.905 19.457 ;
     RECT  10.515 19.187 10.605 19.457 ;
     RECT  13.215 19.187 13.305 19.457 ;
     RECT  15.915 19.187 16.005 19.457 ;
     RECT  29.415 19.373 31.014 19.457 ;
     RECT  32.115 19.277 32.205 19.457 ;
     RECT  34.815 19.187 34.905 19.457 ;
     RECT  37.515 19.187 37.605 19.457 ;
     RECT  40.215 19.187 40.305 19.457 ;
     RECT  42.915 19.187 43.005 19.457 ;
     RECT  45.615 19.187 45.705 19.457 ;
     RECT  48.315 19.187 48.405 19.457 ;
     RECT  51.015 19.187 51.105 19.457 ;
     RECT  23.976 19.373 27.738 19.565 ;
     RECT  23.976 19.565 23.994 19.613 ;
     RECT  18.396 19.379 22.302 19.949 ;
     RECT  25.02 19.565 27.738 19.994 ;
     RECT  22.284 19.949 22.302 19.997 ;
     RECT  18.396 19.949 21.15 20.477 ;
     RECT  18.396 20.477 19.206 20.573 ;
     RECT  19.98 20.477 21.15 20.573 ;
     RECT  25.02 19.994 27.486 20.573 ;
     RECT  29.628 19.457 31.014 20.573 ;
     RECT  19.98 20.573 20.466 20.621 ;
     RECT  20.448 20.621 20.466 20.669 ;
     RECT  30.744 20.573 31.014 21.437 ;
     RECT  25.308 20.573 27.486 21.469 ;
     RECT  18.396 20.573 19.062 21.485 ;
     RECT  23.796 21.355 23.814 21.485 ;
     RECT  29.628 20.573 29.646 21.485 ;
     RECT  30.996 21.437 31.014 21.485 ;
     RECT  25.236 21.469 27.486 21.581 ;
    LAYER M4 ;
     RECT  2.408 2.148 2.512 19.452 ;
     RECT  2.512 2.418 2.704 19.182 ;
     RECT  5.108 2.148 5.212 19.452 ;
     RECT  5.212 2.418 5.404 19.182 ;
     RECT  7.808 2.148 7.912 19.452 ;
     RECT  7.912 2.418 8.104 19.182 ;
     RECT  10.508 2.148 10.612 19.452 ;
     RECT  10.612 2.418 10.804 19.182 ;
     RECT  13.208 2.148 13.312 19.452 ;
     RECT  13.312 2.418 13.504 19.182 ;
     RECT  15.908 2.148 16.012 19.452 ;
     RECT  16.012 2.418 16.204 19.182 ;
     RECT  18.421 19.968 18.565 19.992 ;
     RECT  18.385 21.456 18.565 21.48 ;
     RECT  18.349 17.088 18.608 17.112 ;
     RECT  18.373 18.144 18.608 18.696 ;
     RECT  18.565 19.968 18.608 21.48 ;
     RECT  18.608 2.148 18.712 21.48 ;
     RECT  18.712 2.418 18.904 21.48 ;
     RECT  18.904 16.56 19.091 21.48 ;
     RECT  19.091 20.4 19.859 21.48 ;
     RECT  19.897 1.728 19.98 1.752 ;
     RECT  20.069 0.096 20.153 0.12 ;
     RECT  19.091 16.56 20.341 19.368 ;
     RECT  20.341 15.84 20.437 19.368 ;
     RECT  19.98 1.728 20.444 1.8 ;
     RECT  20.444 1.728 20.677 2.28 ;
     RECT  20.677 1.152 20.761 2.28 ;
     RECT  20.761 1.152 20.941 2.328 ;
     RECT  20.941 1.152 21.061 2.376 ;
     RECT  20.905 13.968 21.109 13.992 ;
     RECT  20.437 15.024 21.109 19.368 ;
     RECT  21.061 1.152 21.157 2.904 ;
     RECT  21.109 13.968 21.193 19.368 ;
     RECT  19.859 20.496 21.193 21.48 ;
     RECT  21.157 1.152 21.308 3.048 ;
     RECT  21.193 13.968 21.308 21.48 ;
     RECT  21.308 1.152 21.604 21.48 ;
     RECT  21.604 1.152 21.637 5.112 ;
     RECT  21.604 18.816 21.701 21.48 ;
     RECT  21.637 0.288 21.733 5.112 ;
     RECT  21.733 0.192 21.778 5.112 ;
     RECT  21.701 19.2 21.875 21.48 ;
     RECT  21.875 19.2 22.163 20.568 ;
     RECT  21.778 0.096 22.205 5.112 ;
     RECT  22.205 0.192 22.211 5.112 ;
     RECT  22.211 0.576 22.597 5.112 ;
     RECT  22.163 19.2 22.739 19.992 ;
     RECT  21.604 14.208 22.787 17.64 ;
     RECT  22.739 19.2 22.813 19.368 ;
     RECT  22.787 14.208 22.993 17.064 ;
     RECT  23.353 6.24 23.497 6.264 ;
     RECT  22.993 13.92 23.677 17.064 ;
     RECT  22.597 0.576 23.701 5.208 ;
     RECT  23.497 6.24 23.701 6.696 ;
     RECT  22.885 21.408 23.741 21.432 ;
     RECT  23.741 21.408 23.756 21.48 ;
     RECT  23.756 21.36 23.825 21.48 ;
     RECT  23.825 21.36 23.939 21.432 ;
     RECT  23.701 0.576 23.941 6.696 ;
     RECT  23.939 21.36 23.941 21.384 ;
     RECT  22.813 18.24 23.965 19.368 ;
     RECT  23.941 0.192 24.008 6.696 ;
     RECT  23.677 13.632 24.008 17.064 ;
     RECT  23.965 18.24 24.008 19.608 ;
     RECT  24.008 0.192 24.083 19.608 ;
     RECT  24.083 0.192 24.253 19.56 ;
     RECT  24.253 0.096 24.304 19.56 ;
     RECT  24.304 12.528 24.419 19.56 ;
     RECT  23.941 21.12 24.467 21.384 ;
     RECT  24.419 12.816 24.509 19.56 ;
     RECT  24.467 21.12 24.515 21.24 ;
     RECT  24.509 12.816 24.611 19.368 ;
     RECT  24.304 0.096 24.649 5.208 ;
     RECT  24.611 12.816 24.755 15.432 ;
     RECT  24.649 0.048 25.085 5.208 ;
     RECT  25.085 0.528 25.553 4.152 ;
     RECT  24.755 12.816 25.589 15.384 ;
     RECT  25.589 15.024 25.724 15.384 ;
     RECT  24.611 16.416 25.724 19.368 ;
     RECT  25.009 20.544 25.907 20.568 ;
     RECT  25.724 15.024 26.233 19.368 ;
     RECT  25.553 0.528 26.245 3.432 ;
     RECT  26.245 0.096 26.549 3.432 ;
     RECT  26.233 15.024 26.593 19.416 ;
     RECT  26.593 15.024 26.677 19.608 ;
     RECT  26.549 0.096 26.708 4.008 ;
     RECT  25.085 5.184 26.708 5.208 ;
     RECT  25.589 12.816 26.708 13.848 ;
     RECT  26.677 15.024 26.708 19.452 ;
     RECT  26.708 0.096 26.812 19.452 ;
     RECT  26.581 21.408 26.917 21.432 ;
     RECT  26.812 0.096 27.004 19.368 ;
     RECT  27.004 0.096 27.025 3.48 ;
     RECT  27.004 12.816 27.395 17.112 ;
     RECT  27.004 6.24 27.433 6.84 ;
     RECT  27.004 4.56 27.721 5.16 ;
     RECT  27.025 0.048 27.749 3.48 ;
     RECT  27.721 4.56 27.785 4.584 ;
     RECT  27.433 6.816 28.037 6.84 ;
     RECT  27.749 0.096 28.045 3.48 ;
     RECT  27.395 13.824 28.429 17.112 ;
     RECT  27.004 18.432 28.429 19.368 ;
     RECT  28.045 0.096 29.017 2.616 ;
     RECT  29.017 0.96 29.029 2.616 ;
     RECT  28.133 3.984 29.029 4.008 ;
     RECT  29.029 0.96 29.408 4.008 ;
     RECT  27.395 12.816 29.408 12.84 ;
     RECT  28.429 13.824 29.408 19.368 ;
     RECT  29.408 0.96 29.512 19.452 ;
     RECT  26.917 20.544 29.617 21.432 ;
     RECT  29.512 0.96 29.704 19.368 ;
     RECT  29.704 0.96 30.017 2.856 ;
     RECT  30.017 0.96 30.035 2.712 ;
     RECT  30.229 0.576 30.337 0.6 ;
     RECT  30.035 1.632 30.485 2.712 ;
     RECT  30.485 1.632 30.707 2.568 ;
     RECT  29.617 20.544 30.803 21.48 ;
     RECT  30.337 0.096 30.899 0.6 ;
     RECT  29.704 12.816 30.899 12.84 ;
     RECT  30.803 21.456 31.025 21.48 ;
     RECT  30.707 1.68 31.453 2.568 ;
     RECT  30.899 0.144 31.676 0.6 ;
     RECT  31.453 1.68 31.676 2.664 ;
     RECT  31.676 0.144 31.885 2.664 ;
     RECT  31.885 0.096 32.108 2.664 ;
     RECT  29.704 17.376 32.108 19.368 ;
     RECT  32.108 0.096 32.212 19.452 ;
     RECT  32.212 0.096 32.404 19.182 ;
     RECT  32.404 0.096 34.621 2.568 ;
     RECT  34.621 0.096 34.808 2.856 ;
     RECT  34.808 0.096 34.912 19.452 ;
     RECT  34.912 0.096 35.104 19.182 ;
     RECT  35.104 0.096 35.777 2.856 ;
     RECT  35.777 0.096 35.891 2.808 ;
     RECT  35.891 0.48 37.105 2.808 ;
     RECT  37.105 0.144 37.508 2.808 ;
     RECT  37.508 0.144 37.612 19.452 ;
     RECT  37.612 0.144 37.729 1.224 ;
     RECT  37.612 2.418 37.804 19.182 ;
     RECT  37.729 0.144 37.811 0.84 ;
     RECT  37.811 0.144 37.861 0.6 ;
     RECT  37.861 0.096 38.233 0.6 ;
     RECT  38.233 0.576 38.305 0.6 ;
     RECT  40.208 2.148 40.312 19.452 ;
     RECT  40.312 2.418 40.504 19.182 ;
     RECT  42.908 2.148 43.012 19.452 ;
     RECT  43.012 2.418 43.204 19.182 ;
     RECT  45.608 2.148 45.712 19.452 ;
     RECT  45.712 2.418 45.904 19.182 ;
     RECT  48.308 2.148 48.412 19.452 ;
     RECT  48.412 2.418 48.604 19.182 ;
     RECT  51.008 2.148 51.112 19.452 ;
     RECT  51.112 2.418 51.304 19.182 ;
    LAYER M5 ;
     RECT  19.92 0.016 38.28 0.611 ;
     RECT  19.92 0.611 37.8 0.851 ;
     RECT  19.92 0.851 37.704 1.763 ;
     RECT  20.016 1.763 32.412 1.811 ;
     RECT  33.648 1.763 33.672 1.811 ;
     RECT  34.8 1.763 36.264 1.811 ;
     RECT  34.8 1.811 35.304 1.859 ;
     RECT  2.4 2.137 2.52 2.151 ;
     RECT  5.1 2.137 5.22 2.151 ;
     RECT  7.8 2.137 7.92 2.151 ;
     RECT  10.5 2.137 10.62 2.151 ;
     RECT  13.2 2.137 13.32 2.151 ;
     RECT  15.9 2.137 16.02 2.151 ;
     RECT  18.6 2.137 18.72 2.151 ;
     RECT  37.5 1.763 37.704 2.151 ;
     RECT  40.2 2.137 40.32 2.151 ;
     RECT  42.9 2.137 43.02 2.151 ;
     RECT  45.6 2.137 45.72 2.151 ;
     RECT  48.3 2.137 48.42 2.151 ;
     RECT  51 2.137 51.12 2.151 ;
     RECT  20.496 1.811 32.412 2.195 ;
     RECT  20.496 2.195 30.984 2.291 ;
     RECT  20.784 2.291 29.712 2.339 ;
     RECT  21.072 2.339 29.712 2.915 ;
     RECT  21.168 2.915 29.712 3.059 ;
     RECT  21.3 3.059 29.712 3.443 ;
     RECT  21.3 3.443 25.032 3.635 ;
     RECT  21.3 3.635 24.552 3.827 ;
     RECT  21.3 3.827 24.504 4.019 ;
     RECT  26.592 3.443 29.712 4.019 ;
     RECT  21.3 4.019 24.456 4.211 ;
     RECT  21.3 4.211 24.408 4.595 ;
     RECT  22.608 4.595 24.408 5.075 ;
     RECT  26.7 4.019 27.672 5.171 ;
     RECT  22.608 5.075 22.632 5.219 ;
     RECT  23.712 5.075 24.408 6.229 ;
     RECT  26.7 5.171 27.012 6.229 ;
     RECT  23.52 6.229 24.408 12.901 ;
     RECT  26.7 6.229 27.384 13.477 ;
     RECT  21.3 4.595 21.612 13.957 ;
     RECT  21.12 13.957 21.612 14.197 ;
     RECT  21.12 14.197 22.2 14.245 ;
     RECT  23.52 12.901 25.176 14.245 ;
     RECT  21.12 14.245 25.176 14.773 ;
     RECT  26.208 13.477 27.384 14.773 ;
     RECT  21.12 14.773 27.624 15.013 ;
     RECT  29.4 4.019 29.712 15.349 ;
     RECT  21.072 15.013 27.624 15.827 ;
     RECT  21.072 15.827 27.288 15.829 ;
     RECT  20.352 15.829 27.288 16.595 ;
     RECT  18.6 2.151 18.912 17.077 ;
     RECT  20.688 16.595 27.288 17.077 ;
     RECT  29.28 15.349 29.712 17.077 ;
     RECT  20.688 17.077 27.816 17.653 ;
     RECT  29.04 17.077 29.712 18.131 ;
     RECT  29.4 18.131 29.712 18.181 ;
     RECT  30.864 12.805 30.888 18.181 ;
     RECT  20.496 17.653 27.816 18.229 ;
     RECT  18.384 17.077 18.912 18.707 ;
     RECT  18.6 18.707 18.912 18.757 ;
     RECT  20.4 18.229 27.816 18.757 ;
     RECT  18.6 18.757 27.816 18.997 ;
     RECT  2.4 2.151 2.712 19.449 ;
     RECT  5.1 2.151 5.412 19.449 ;
     RECT  7.8 2.151 8.112 19.449 ;
     RECT  10.5 2.151 10.812 19.449 ;
     RECT  13.2 2.151 13.512 19.449 ;
     RECT  15.9 2.151 16.212 19.449 ;
     RECT  32.1 2.195 32.412 19.449 ;
     RECT  34.8 1.859 35.112 19.449 ;
     RECT  37.5 2.151 37.812 19.449 ;
     RECT  40.2 2.151 40.512 19.449 ;
     RECT  42.9 2.151 43.212 19.449 ;
     RECT  45.6 2.151 45.912 19.449 ;
     RECT  48.3 2.151 48.612 19.449 ;
     RECT  51 2.151 51.312 19.449 ;
     RECT  2.4 19.449 2.52 19.463 ;
     RECT  5.1 19.449 5.22 19.463 ;
     RECT  7.8 19.449 7.92 19.463 ;
     RECT  10.5 19.449 10.62 19.463 ;
     RECT  13.2 19.449 13.32 19.463 ;
     RECT  15.9 19.449 16.02 19.463 ;
     RECT  18.6 18.997 27.912 19.463 ;
     RECT  29.4 18.181 30.888 19.463 ;
     RECT  32.1 19.449 32.22 19.463 ;
     RECT  34.8 19.449 34.92 19.463 ;
     RECT  37.5 19.449 37.62 19.463 ;
     RECT  40.2 19.449 40.32 19.463 ;
     RECT  42.9 19.449 43.02 19.463 ;
     RECT  45.6 19.449 45.72 19.463 ;
     RECT  48.3 19.449 48.42 19.463 ;
     RECT  51 19.449 51.12 19.463 ;
     RECT  30.192 19.463 30.888 21.445 ;
     RECT  18.768 19.463 27.912 21.584 ;
     RECT  30.096 21.445 30.984 21.584 ;
  END
END hbfd_lh_136_NS_f2
END LIBRARY
